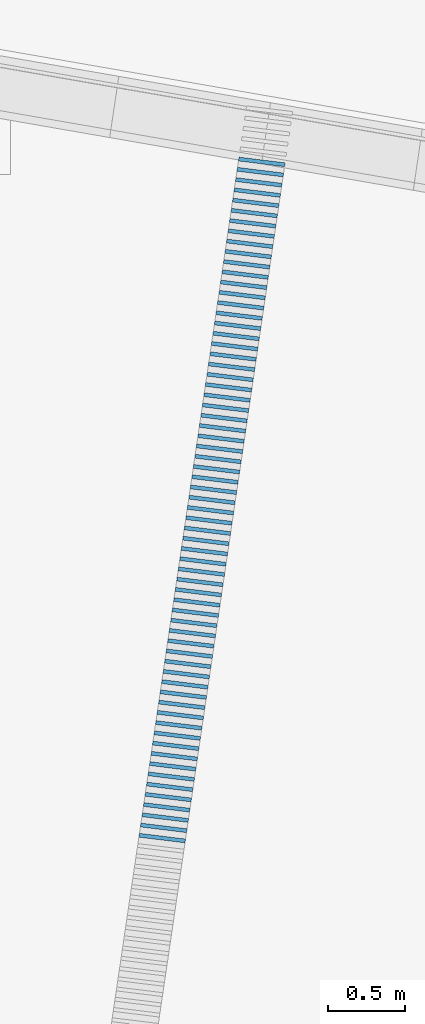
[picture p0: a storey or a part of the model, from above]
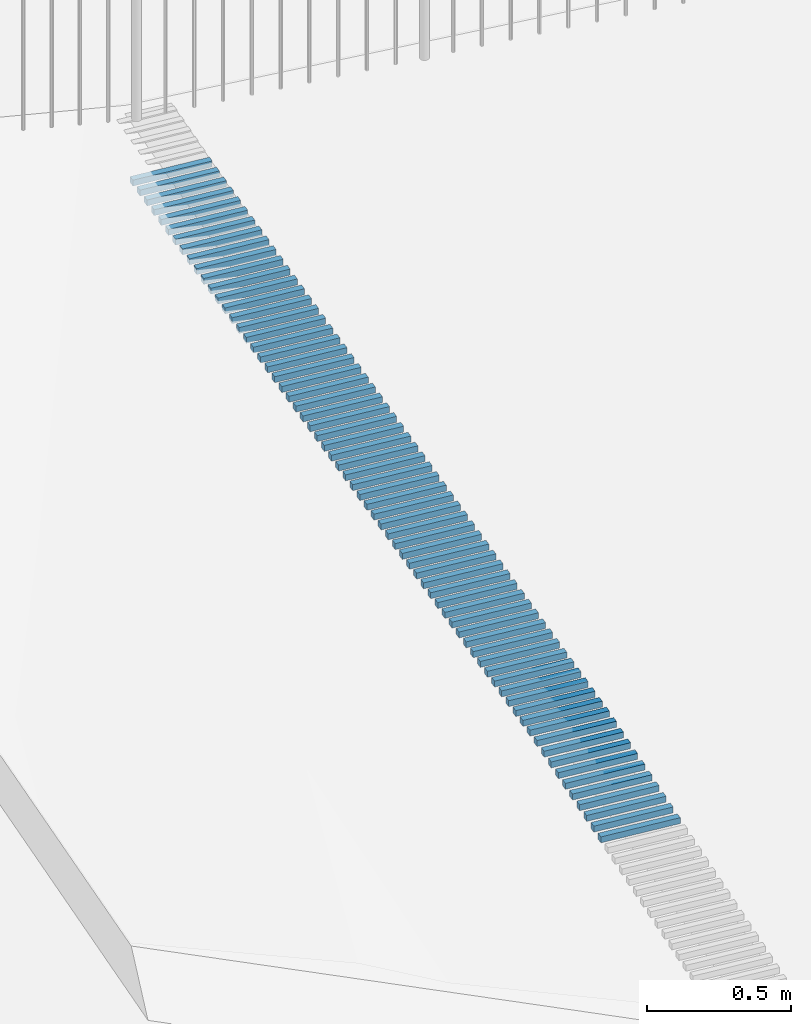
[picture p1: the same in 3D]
Properties of the parts of a building model (IFC4), part 2 of 4

# IfcBuildingElementProxy: Limite north · gabião 20 · pedra aparente
Pset_CasaProvenance - DesignSource: Casa Sobreposta / configuration.json; ReferenceFile: 260617_CasaDFL_Estrutura_Terreno.ifc; ConstructionBasis: DESIGN_ASSUMPTION; Note: R07 concept geometry; dimensions and connections not structurally verified.

# IfcBuildingElementProxy: Limite north · gabião 21 · cesto galvanizado
In: Lares · Rua das Mercês · artigo 4771
PredefinedType: USERDEFINED; Material: Aço galvanizado / Stahl verzinkt
Pset_CasaProvenance - DesignSource: Casa Sobreposta / configuration.json; ReferenceFile: 260617_CasaDFL_Estrutura_Terreno.ifc; ConstructionBasis: DESIGN_ASSUMPTION; Note: R07 concept geometry; dimensions and connections not structurally verified.

# IfcBuildingElementProxy: Limite north · gabião 21 · pedra aparente
In: Lares · Rua das Mercês · artigo 4771
PredefinedType: USERDEFINED; Material: Gabião · pedra irregular
Pset_CasaProvenance - DesignSource: Casa Sobreposta / configuration.json; ReferenceFile: 260617_CasaDFL_Estrutura_Terreno.ifc; ConstructionBasis: DESIGN_ASSUMPTION; Note: R07 concept geometry; dimensions and connections not structurally verified.

# IfcBuildingElementProxy: Limite north · gabião 22 · cesto galvanizado
In: Lares · Rua das Mercês · artigo 4771
PredefinedType: USERDEFINED; Material: Aço galvanizado / Stahl verzinkt
Pset_CasaProvenance - DesignSource: Casa Sobreposta / configuration.json; ReferenceFile: 260617_CasaDFL_Estrutura_Terreno.ifc; ConstructionBasis: DESIGN_ASSUMPTION; Note: R07 concept geometry; dimensions and connections not structurally verified.

# IfcBuildingElementProxy: Limite north · gabião 22 · pedra aparente
In: Lares · Rua das Mercês · artigo 4771
PredefinedType: USERDEFINED; Material: Gabião · pedra irregular
Pset_CasaProvenance - DesignSource: Casa Sobreposta / configuration.json; ReferenceFile: 260617_CasaDFL_Estrutura_Terreno.ifc; ConstructionBasis: DESIGN_ASSUMPTION; Note: R07 concept geometry; dimensions and connections not structurally verified.

# IfcBuildingElementProxy: Limite north · gabião 23 · cesto galvanizado
In: Lares · Rua das Mercês · artigo 4771
PredefinedType: USERDEFINED; Material: Aço galvanizado / Stahl verzinkt
Pset_CasaProvenance - DesignSource: Casa Sobreposta / configuration.json; ReferenceFile: 260617_CasaDFL_Estrutura_Terreno.ifc; ConstructionBasis: DESIGN_ASSUMPTION; Note: R07 concept geometry; dimensions and connections not structurally verified.

# IfcBuildingElementProxy: Limite north · gabião 23 · pedra aparente
In: Lares · Rua das Mercês · artigo 4771
PredefinedType: USERDEFINED; Material: Gabião · pedra irregular
Pset_CasaProvenance - DesignSource: Casa Sobreposta / configuration.json; ReferenceFile: 260617_CasaDFL_Estrutura_Terreno.ifc; ConstructionBasis: DESIGN_ASSUMPTION; Note: R07 concept geometry; dimensions and connections not structurally verified.

# IfcBuildingElementProxy: Limite north · gabião 24 · cesto galvanizado
In: Lares · Rua das Mercês · artigo 4771
PredefinedType: USERDEFINED; Material: Aço galvanizado / Stahl verzinkt
Pset_CasaProvenance - DesignSource: Casa Sobreposta / configuration.json; ReferenceFile: 260617_CasaDFL_Estrutura_Terreno.ifc; ConstructionBasis: DESIGN_ASSUMPTION; Note: R07 concept geometry; dimensions and connections not structurally verified.

# IfcBuildingElementProxy: Limite north · gabião 24 · pedra aparente
In: Lares · Rua das Mercês · artigo 4771
PredefinedType: USERDEFINED; Material: Gabião · pedra irregular
Pset_CasaProvenance - DesignSource: Casa Sobreposta / configuration.json; ReferenceFile: 260617_CasaDFL_Estrutura_Terreno.ifc; ConstructionBasis: DESIGN_ASSUMPTION; Note: R07 concept geometry; dimensions and connections not structurally verified.

# IfcBuildingElementProxy: Limite north · gabião 25 · cesto galvanizado
In: Lares · Rua das Mercês · artigo 4771
PredefinedType: USERDEFINED; Material: Aço galvanizado / Stahl verzinkt
Pset_CasaProvenance - DesignSource: Casa Sobreposta / configuration.json; ReferenceFile: 260617_CasaDFL_Estrutura_Terreno.ifc; ConstructionBasis: DESIGN_ASSUMPTION; Note: R07 concept geometry; dimensions and connections not structurally verified.

# IfcBuildingElementProxy: Limite north · gabião 25 · pedra aparente
In: Lares · Rua das Mercês · artigo 4771
PredefinedType: USERDEFINED; Material: Gabião · pedra irregular
Pset_CasaProvenance - DesignSource: Casa Sobreposta / configuration.json; ReferenceFile: 260617_CasaDFL_Estrutura_Terreno.ifc; ConstructionBasis: DESIGN_ASSUMPTION; Note: R07 concept geometry; dimensions and connections not structurally verified.

# IfcBuildingElementProxy: Limite north · gabião 26 · cesto galvanizado
In: Lares · Rua das Mercês · artigo 4771
PredefinedType: USERDEFINED; Material: Aço galvanizado / Stahl verzinkt
Pset_CasaProvenance - DesignSource: Casa Sobreposta / configuration.json; ReferenceFile: 260617_CasaDFL_Estrutura_Terreno.ifc; ConstructionBasis: DESIGN_ASSUMPTION; Note: R07 concept geometry; dimensions and connections not structurally verified.

# IfcBuildingElementProxy: Limite north · gabião 26 · pedra aparente
In: Lares · Rua das Mercês · artigo 4771
PredefinedType: USERDEFINED; Material: Gabião · pedra irregular
Pset_CasaProvenance - DesignSource: Casa Sobreposta / configuration.json; ReferenceFile: 260617_CasaDFL_Estrutura_Terreno.ifc; ConstructionBasis: DESIGN_ASSUMPTION; Note: R07 concept geometry; dimensions and connections not structurally verified.

# IfcBuildingElementProxy: Limite north · gabião 27 · cesto galvanizado
In: Lares · Rua das Mercês · artigo 4771
PredefinedType: USERDEFINED; Material: Aço galvanizado / Stahl verzinkt
Pset_CasaProvenance - DesignSource: Casa Sobreposta / configuration.json; ReferenceFile: 260617_CasaDFL_Estrutura_Terreno.ifc; ConstructionBasis: DESIGN_ASSUMPTION; Note: R07 concept geometry; dimensions and connections not structurally verified.

# IfcBuildingElementProxy: Limite north · gabião 27 · pedra aparente
In: Lares · Rua das Mercês · artigo 4771
PredefinedType: USERDEFINED; Material: Gabião · pedra irregular
Pset_CasaProvenance - DesignSource: Casa Sobreposta / configuration.json; ReferenceFile: 260617_CasaDFL_Estrutura_Terreno.ifc; ConstructionBasis: DESIGN_ASSUMPTION; Note: R07 concept geometry; dimensions and connections not structurally verified.

# IfcBuildingElementProxy: Limite north · gabião 4 · cesto galvanizado
In: Lares · Rua das Mercês · artigo 4771
PredefinedType: USERDEFINED; Material: Aço galvanizado / Stahl verzinkt
Pset_CasaProvenance - DesignSource: Casa Sobreposta / configuration.json; ReferenceFile: 260617_CasaDFL_Estrutura_Terreno.ifc; ConstructionBasis: DESIGN_ASSUMPTION; Note: R07 concept geometry; dimensions and connections not structurally verified.

# IfcBuildingElementProxy: Limite north · gabião 4 · pedra aparente
In: Lares · Rua das Mercês · artigo 4771
PredefinedType: USERDEFINED; Material: Gabião · pedra irregular
Pset_CasaProvenance - DesignSource: Casa Sobreposta / configuration.json; ReferenceFile: 260617_CasaDFL_Estrutura_Terreno.ifc; ConstructionBasis: DESIGN_ASSUMPTION; Note: R07 concept geometry; dimensions and connections not structurally verified.

# IfcBuildingElementProxy: Limite north · gabião 5 · cesto galvanizado
In: Lares · Rua das Mercês · artigo 4771
PredefinedType: USERDEFINED; Material: Aço galvanizado / Stahl verzinkt
Pset_CasaProvenance - DesignSource: Casa Sobreposta / configuration.json; ReferenceFile: 260617_CasaDFL_Estrutura_Terreno.ifc; ConstructionBasis: DESIGN_ASSUMPTION; Note: R07 concept geometry; dimensions and connections not structurally verified.

# IfcBuildingElementProxy: Limite north · gabião 5 · pedra aparente
In: Lares · Rua das Mercês · artigo 4771
PredefinedType: USERDEFINED; Material: Gabião · pedra irregular
Pset_CasaProvenance - DesignSource: Casa Sobreposta / configuration.json; ReferenceFile: 260617_CasaDFL_Estrutura_Terreno.ifc; ConstructionBasis: DESIGN_ASSUMPTION; Note: R07 concept geometry; dimensions and connections not structurally verified.

# IfcBuildingElementProxy: Limite north · gabião 6 · cesto galvanizado
In: Lares · Rua das Mercês · artigo 4771
PredefinedType: USERDEFINED; Material: Aço galvanizado / Stahl verzinkt
Pset_CasaProvenance - DesignSource: Casa Sobreposta / configuration.json; ReferenceFile: 260617_CasaDFL_Estrutura_Terreno.ifc; ConstructionBasis: DESIGN_ASSUMPTION; Note: R07 concept geometry; dimensions and connections not structurally verified.

# IfcBuildingElementProxy: Limite north · gabião 6 · pedra aparente
In: Lares · Rua das Mercês · artigo 4771
PredefinedType: USERDEFINED; Material: Gabião · pedra irregular
Pset_CasaProvenance - DesignSource: Casa Sobreposta / configuration.json; ReferenceFile: 260617_CasaDFL_Estrutura_Terreno.ifc; ConstructionBasis: DESIGN_ASSUMPTION; Note: R07 concept geometry; dimensions and connections not structurally verified.

# IfcBuildingElementProxy: Limite north · gabião 7 · cesto galvanizado
In: Lares · Rua das Mercês · artigo 4771
PredefinedType: USERDEFINED; Material: Aço galvanizado / Stahl verzinkt
Pset_CasaProvenance - DesignSource: Casa Sobreposta / configuration.json; ReferenceFile: 260617_CasaDFL_Estrutura_Terreno.ifc; ConstructionBasis: DESIGN_ASSUMPTION; Note: R07 concept geometry; dimensions and connections not structurally verified.

# IfcBuildingElementProxy: Limite north · gabião 7 · pedra aparente
In: Lares · Rua das Mercês · artigo 4771
PredefinedType: USERDEFINED; Material: Gabião · pedra irregular
Pset_CasaProvenance - DesignSource: Casa Sobreposta / configuration.json; ReferenceFile: 260617_CasaDFL_Estrutura_Terreno.ifc; ConstructionBasis: DESIGN_ASSUMPTION; Note: R07 concept geometry; dimensions and connections not structurally verified.

# IfcBuildingElementProxy: Limite north · gabião 8 · cesto galvanizado
In: Lares · Rua das Mercês · artigo 4771
PredefinedType: USERDEFINED; Material: Aço galvanizado / Stahl verzinkt
Pset_CasaProvenance - DesignSource: Casa Sobreposta / configuration.json; ReferenceFile: 260617_CasaDFL_Estrutura_Terreno.ifc; ConstructionBasis: DESIGN_ASSUMPTION; Note: R07 concept geometry; dimensions and connections not structurally verified.

# IfcBuildingElementProxy: Limite north · gabião 8 · pedra aparente
In: Lares · Rua das Mercês · artigo 4771
PredefinedType: USERDEFINED; Material: Gabião · pedra irregular
Pset_CasaProvenance - DesignSource: Casa Sobreposta / configuration.json; ReferenceFile: 260617_CasaDFL_Estrutura_Terreno.ifc; ConstructionBasis: DESIGN_ASSUMPTION; Note: R07 concept geometry; dimensions and connections not structurally verified.

# IfcBuildingElementProxy: Limite north · gabião 9 · cesto galvanizado
In: Lares · Rua das Mercês · artigo 4771
PredefinedType: USERDEFINED; Material: Aço galvanizado / Stahl verzinkt
Pset_CasaProvenance - DesignSource: Casa Sobreposta / configuration.json; ReferenceFile: 260617_CasaDFL_Estrutura_Terreno.ifc; ConstructionBasis: DESIGN_ASSUMPTION; Note: R07 concept geometry; dimensions and connections not structurally verified.

# IfcBuildingElementProxy: Limite north · gabião 9 · pedra aparente
In: Lares · Rua das Mercês · artigo 4771
PredefinedType: USERDEFINED; Material: Gabião · pedra irregular
Pset_CasaProvenance - DesignSource: Casa Sobreposta / configuration.json; ReferenceFile: 260617_CasaDFL_Estrutura_Terreno.ifc; ConstructionBasis: DESIGN_ASSUMPTION; Note: R07 concept geometry; dimensions and connections not structurally verified.

# IfcBuildingElementProxy: Limite north · vala de interceção (37)
In: Lares · Rua das Mercês · artigo 4771
PredefinedType: USERDEFINED; Material: Brita drenante
Pset_CasaProvenance - DesignSource: Casa Sobreposta / configuration.json; ReferenceFile: 260617_CasaDFL_Estrutura_Terreno.ifc; ConstructionBasis: DESIGN_ASSUMPTION

# IfcBuildingElementProxy: Limite south · gabião 1 · cesto galvanizado
In: Lares · Rua das Mercês · artigo 4771
PredefinedType: USERDEFINED; Material: Aço galvanizado / Stahl verzinkt
Pset_CasaProvenance - DesignSource: Casa Sobreposta / configuration.json; ReferenceFile: 260617_CasaDFL_Estrutura_Terreno.ifc; ConstructionBasis: DESIGN_ASSUMPTION; Note: R07 concept geometry; dimensions and connections not structurally verified.

# IfcBuildingElementProxy: Limite south · gabião 1 · pedra aparente
In: Lares · Rua das Mercês · artigo 4771
PredefinedType: USERDEFINED; Material: Gabião · pedra irregular
Pset_CasaProvenance - DesignSource: Casa Sobreposta / configuration.json; ReferenceFile: 260617_CasaDFL_Estrutura_Terreno.ifc; ConstructionBasis: DESIGN_ASSUMPTION; Note: R07 concept geometry; dimensions and connections not structurally verified.

# IfcBuildingElementProxy: Limite south · gabião 10 · cesto galvanizado
In: Lares · Rua das Mercês · artigo 4771
PredefinedType: USERDEFINED; Material: Aço galvanizado / Stahl verzinkt
Pset_CasaProvenance - DesignSource: Casa Sobreposta / configuration.json; ReferenceFile: 260617_CasaDFL_Estrutura_Terreno.ifc; ConstructionBasis: DESIGN_ASSUMPTION; Note: R07 concept geometry; dimensions and connections not structurally verified.

# IfcBuildingElementProxy: Limite south · gabião 10 · pedra aparente
In: Lares · Rua das Mercês · artigo 4771
PredefinedType: USERDEFINED; Material: Gabião · pedra irregular
Pset_CasaProvenance - DesignSource: Casa Sobreposta / configuration.json; ReferenceFile: 260617_CasaDFL_Estrutura_Terreno.ifc; ConstructionBasis: DESIGN_ASSUMPTION; Note: R07 concept geometry; dimensions and connections not structurally verified.

# IfcBuildingElementProxy: Limite south · gabião 11 · cesto galvanizado
In: Lares · Rua das Mercês · artigo 4771
PredefinedType: USERDEFINED; Material: Aço galvanizado / Stahl verzinkt
Pset_CasaProvenance - DesignSource: Casa Sobreposta / configuration.json; ReferenceFile: 260617_CasaDFL_Estrutura_Terreno.ifc; ConstructionBasis: DESIGN_ASSUMPTION; Note: R07 concept geometry; dimensions and connections not structurally verified.

# IfcBuildingElementProxy: Limite south · gabião 11 · pedra aparente
In: Lares · Rua das Mercês · artigo 4771
PredefinedType: USERDEFINED; Material: Gabião · pedra irregular
Pset_CasaProvenance - DesignSource: Casa Sobreposta / configuration.json; ReferenceFile: 260617_CasaDFL_Estrutura_Terreno.ifc; ConstructionBasis: DESIGN_ASSUMPTION; Note: R07 concept geometry; dimensions and connections not structurally verified.

# IfcBuildingElementProxy: Limite south · gabião 12 · cesto galvanizado
In: Lares · Rua das Mercês · artigo 4771
PredefinedType: USERDEFINED; Material: Aço galvanizado / Stahl verzinkt
Pset_CasaProvenance - DesignSource: Casa Sobreposta / configuration.json; ReferenceFile: 260617_CasaDFL_Estrutura_Terreno.ifc; ConstructionBasis: DESIGN_ASSUMPTION; Note: R07 concept geometry; dimensions and connections not structurally verified.

# IfcBuildingElementProxy: Limite south · gabião 12 · pedra aparente
In: Lares · Rua das Mercês · artigo 4771
PredefinedType: USERDEFINED; Material: Gabião · pedra irregular
Pset_CasaProvenance - DesignSource: Casa Sobreposta / configuration.json; ReferenceFile: 260617_CasaDFL_Estrutura_Terreno.ifc; ConstructionBasis: DESIGN_ASSUMPTION; Note: R07 concept geometry; dimensions and connections not structurally verified.

# IfcBuildingElementProxy: Limite south · gabião 13 · cesto galvanizado
In: Lares · Rua das Mercês · artigo 4771
PredefinedType: USERDEFINED; Material: Aço galvanizado / Stahl verzinkt
Pset_CasaProvenance - DesignSource: Casa Sobreposta / configuration.json; ReferenceFile: 260617_CasaDFL_Estrutura_Terreno.ifc; ConstructionBasis: DESIGN_ASSUMPTION; Note: R07 concept geometry; dimensions and connections not structurally verified.

# IfcBuildingElementProxy: Limite south · gabião 13 · pedra aparente
In: Lares · Rua das Mercês · artigo 4771
PredefinedType: USERDEFINED; Material: Gabião · pedra irregular
Pset_CasaProvenance - DesignSource: Casa Sobreposta / configuration.json; ReferenceFile: 260617_CasaDFL_Estrutura_Terreno.ifc; ConstructionBasis: DESIGN_ASSUMPTION; Note: R07 concept geometry; dimensions and connections not structurally verified.

# IfcBuildingElementProxy: Limite south · gabião 14 · cesto galvanizado
In: Lares · Rua das Mercês · artigo 4771
PredefinedType: USERDEFINED; Material: Aço galvanizado / Stahl verzinkt
Pset_CasaProvenance - DesignSource: Casa Sobreposta / configuration.json; ReferenceFile: 260617_CasaDFL_Estrutura_Terreno.ifc; ConstructionBasis: DESIGN_ASSUMPTION; Note: R07 concept geometry; dimensions and connections not structurally verified.

# IfcBuildingElementProxy: Limite south · gabião 14 · pedra aparente
In: Lares · Rua das Mercês · artigo 4771
PredefinedType: USERDEFINED; Material: Gabião · pedra irregular
Pset_CasaProvenance - DesignSource: Casa Sobreposta / configuration.json; ReferenceFile: 260617_CasaDFL_Estrutura_Terreno.ifc; ConstructionBasis: DESIGN_ASSUMPTION; Note: R07 concept geometry; dimensions and connections not structurally verified.

# IfcBuildingElementProxy: Limite south · gabião 15 · cesto galvanizado
In: Lares · Rua das Mercês · artigo 4771
PredefinedType: USERDEFINED; Material: Aço galvanizado / Stahl verzinkt
Pset_CasaProvenance - DesignSource: Casa Sobreposta / configuration.json; ReferenceFile: 260617_CasaDFL_Estrutura_Terreno.ifc; ConstructionBasis: DESIGN_ASSUMPTION; Note: R07 concept geometry; dimensions and connections not structurally verified.

# IfcBuildingElementProxy: Limite south · gabião 15 · pedra aparente
In: Lares · Rua das Mercês · artigo 4771
PredefinedType: USERDEFINED; Material: Gabião · pedra irregular
Pset_CasaProvenance - DesignSource: Casa Sobreposta / configuration.json; ReferenceFile: 260617_CasaDFL_Estrutura_Terreno.ifc; ConstructionBasis: DESIGN_ASSUMPTION; Note: R07 concept geometry; dimensions and connections not structurally verified.

# IfcBuildingElementProxy: Limite south · gabião 16 · cesto galvanizado
In: Lares · Rua das Mercês · artigo 4771
PredefinedType: USERDEFINED; Material: Aço galvanizado / Stahl verzinkt
Pset_CasaProvenance - DesignSource: Casa Sobreposta / configuration.json; ReferenceFile: 260617_CasaDFL_Estrutura_Terreno.ifc; ConstructionBasis: DESIGN_ASSUMPTION; Note: R07 concept geometry; dimensions and connections not structurally verified.

# IfcBuildingElementProxy: Limite south · gabião 16 · pedra aparente
In: Lares · Rua das Mercês · artigo 4771
PredefinedType: USERDEFINED; Material: Gabião · pedra irregular
Pset_CasaProvenance - DesignSource: Casa Sobreposta / configuration.json; ReferenceFile: 260617_CasaDFL_Estrutura_Terreno.ifc; ConstructionBasis: DESIGN_ASSUMPTION; Note: R07 concept geometry; dimensions and connections not structurally verified.

# IfcBuildingElementProxy: Limite south · gabião 17 · cesto galvanizado
In: Lares · Rua das Mercês · artigo 4771
PredefinedType: USERDEFINED; Material: Aço galvanizado / Stahl verzinkt
Pset_CasaProvenance - DesignSource: Casa Sobreposta / configuration.json; ReferenceFile: 260617_CasaDFL_Estrutura_Terreno.ifc; ConstructionBasis: DESIGN_ASSUMPTION; Note: R07 concept geometry; dimensions and connections not structurally verified.

# IfcBuildingElementProxy: Limite south · gabião 17 · pedra aparente
In: Lares · Rua das Mercês · artigo 4771
PredefinedType: USERDEFINED; Material: Gabião · pedra irregular
Pset_CasaProvenance - DesignSource: Casa Sobreposta / configuration.json; ReferenceFile: 260617_CasaDFL_Estrutura_Terreno.ifc; ConstructionBasis: DESIGN_ASSUMPTION; Note: R07 concept geometry; dimensions and connections not structurally verified.

# IfcBuildingElementProxy: Limite south · gabião 18 · cesto galvanizado
In: Lares · Rua das Mercês · artigo 4771
PredefinedType: USERDEFINED; Material: Aço galvanizado / Stahl verzinkt
Pset_CasaProvenance - DesignSource: Casa Sobreposta / configuration.json; ReferenceFile: 260617_CasaDFL_Estrutura_Terreno.ifc; ConstructionBasis: DESIGN_ASSUMPTION; Note: R07 concept geometry; dimensions and connections not structurally verified.

# IfcBuildingElementProxy: Limite south · gabião 18 · pedra aparente
In: Lares · Rua das Mercês · artigo 4771
PredefinedType: USERDEFINED; Material: Gabião · pedra irregular
Pset_CasaProvenance - DesignSource: Casa Sobreposta / configuration.json; ReferenceFile: 260617_CasaDFL_Estrutura_Terreno.ifc; ConstructionBasis: DESIGN_ASSUMPTION; Note: R07 concept geometry; dimensions and connections not structurally verified.

# IfcBuildingElementProxy: Limite south · gabião 19 · cesto galvanizado
In: Lares · Rua das Mercês · artigo 4771
PredefinedType: USERDEFINED; Material: Aço galvanizado / Stahl verzinkt
Pset_CasaProvenance - DesignSource: Casa Sobreposta / configuration.json; ReferenceFile: 260617_CasaDFL_Estrutura_Terreno.ifc; ConstructionBasis: DESIGN_ASSUMPTION; Note: R07 concept geometry; dimensions and connections not structurally verified.

# IfcBuildingElementProxy: Limite south · gabião 19 · pedra aparente
In: Lares · Rua das Mercês · artigo 4771
PredefinedType: USERDEFINED; Material: Gabião · pedra irregular
Pset_CasaProvenance - DesignSource: Casa Sobreposta / configuration.json; ReferenceFile: 260617_CasaDFL_Estrutura_Terreno.ifc; ConstructionBasis: DESIGN_ASSUMPTION; Note: R07 concept geometry; dimensions and connections not structurally verified.

# IfcBuildingElementProxy: Limite south · gabião 2 · cesto galvanizado
In: Lares · Rua das Mercês · artigo 4771
PredefinedType: USERDEFINED; Material: Aço galvanizado / Stahl verzinkt
Pset_CasaProvenance - DesignSource: Casa Sobreposta / configuration.json; ReferenceFile: 260617_CasaDFL_Estrutura_Terreno.ifc; ConstructionBasis: DESIGN_ASSUMPTION; Note: R07 concept geometry; dimensions and connections not structurally verified.

# IfcBuildingElementProxy: Limite south · gabião 2 · pedra aparente
In: Lares · Rua das Mercês · artigo 4771
PredefinedType: USERDEFINED; Material: Gabião · pedra irregular
Pset_CasaProvenance - DesignSource: Casa Sobreposta / configuration.json; ReferenceFile: 260617_CasaDFL_Estrutura_Terreno.ifc; ConstructionBasis: DESIGN_ASSUMPTION; Note: R07 concept geometry; dimensions and connections not structurally verified.

# IfcBuildingElementProxy: Limite south · gabião 20 · cesto galvanizado
In: Lares · Rua das Mercês · artigo 4771
PredefinedType: USERDEFINED; Material: Aço galvanizado / Stahl verzinkt
Pset_CasaProvenance - DesignSource: Casa Sobreposta / configuration.json; ReferenceFile: 260617_CasaDFL_Estrutura_Terreno.ifc; ConstructionBasis: DESIGN_ASSUMPTION; Note: R07 concept geometry; dimensions and connections not structurally verified.

# IfcBuildingElementProxy: Limite south · gabião 20 · pedra aparente
In: Lares · Rua das Mercês · artigo 4771
PredefinedType: USERDEFINED; Material: Gabião · pedra irregular
Pset_CasaProvenance - DesignSource: Casa Sobreposta / configuration.json; ReferenceFile: 260617_CasaDFL_Estrutura_Terreno.ifc; ConstructionBasis: DESIGN_ASSUMPTION; Note: R07 concept geometry; dimensions and connections not structurally verified.

# IfcBuildingElementProxy: Limite south · gabião 21 · cesto galvanizado
In: Lares · Rua das Mercês · artigo 4771
PredefinedType: USERDEFINED; Material: Aço galvanizado / Stahl verzinkt
Pset_CasaProvenance - DesignSource: Casa Sobreposta / configuration.json; ReferenceFile: 260617_CasaDFL_Estrutura_Terreno.ifc; ConstructionBasis: DESIGN_ASSUMPTION; Note: R07 concept geometry; dimensions and connections not structurally verified.

# IfcBuildingElementProxy: Limite south · gabião 21 · pedra aparente
In: Lares · Rua das Mercês · artigo 4771
PredefinedType: USERDEFINED; Material: Gabião · pedra irregular
Pset_CasaProvenance - DesignSource: Casa Sobreposta / configuration.json; ReferenceFile: 260617_CasaDFL_Estrutura_Terreno.ifc; ConstructionBasis: DESIGN_ASSUMPTION; Note: R07 concept geometry; dimensions and connections not structurally verified.

# IfcBuildingElementProxy: Limite south · gabião 22 · cesto galvanizado
In: Lares · Rua das Mercês · artigo 4771
PredefinedType: USERDEFINED; Material: Aço galvanizado / Stahl verzinkt
Pset_CasaProvenance - DesignSource: Casa Sobreposta / configuration.json; ReferenceFile: 260617_CasaDFL_Estrutura_Terreno.ifc; ConstructionBasis: DESIGN_ASSUMPTION; Note: R07 concept geometry; dimensions and connections not structurally verified.

# IfcBuildingElementProxy: Limite south · gabião 22 · pedra aparente
In: Lares · Rua das Mercês · artigo 4771
PredefinedType: USERDEFINED; Material: Gabião · pedra irregular
Pset_CasaProvenance - DesignSource: Casa Sobreposta / configuration.json; ReferenceFile: 260617_CasaDFL_Estrutura_Terreno.ifc; ConstructionBasis: DESIGN_ASSUMPTION; Note: R07 concept geometry; dimensions and connections not structurally verified.

# IfcBuildingElementProxy: Limite south · gabião 23 · cesto galvanizado
In: Lares · Rua das Mercês · artigo 4771
PredefinedType: USERDEFINED; Material: Aço galvanizado / Stahl verzinkt
Pset_CasaProvenance - DesignSource: Casa Sobreposta / configuration.json; ReferenceFile: 260617_CasaDFL_Estrutura_Terreno.ifc; ConstructionBasis: DESIGN_ASSUMPTION; Note: R07 concept geometry; dimensions and connections not structurally verified.

# IfcBuildingElementProxy: Limite south · gabião 23 · pedra aparente
In: Lares · Rua das Mercês · artigo 4771
PredefinedType: USERDEFINED; Material: Gabião · pedra irregular
Pset_CasaProvenance - DesignSource: Casa Sobreposta / configuration.json; ReferenceFile: 260617_CasaDFL_Estrutura_Terreno.ifc; ConstructionBasis: DESIGN_ASSUMPTION; Note: R07 concept geometry; dimensions and connections not structurally verified.

# IfcBuildingElementProxy: Limite south · gabião 24 · cesto galvanizado
In: Lares · Rua das Mercês · artigo 4771
PredefinedType: USERDEFINED; Material: Aço galvanizado / Stahl verzinkt
Pset_CasaProvenance - DesignSource: Casa Sobreposta / configuration.json; ReferenceFile: 260617_CasaDFL_Estrutura_Terreno.ifc; ConstructionBasis: DESIGN_ASSUMPTION; Note: R07 concept geometry; dimensions and connections not structurally verified.

# IfcBuildingElementProxy: Limite south · gabião 24 · pedra aparente
In: Lares · Rua das Mercês · artigo 4771
PredefinedType: USERDEFINED; Material: Gabião · pedra irregular
Pset_CasaProvenance - DesignSource: Casa Sobreposta / configuration.json; ReferenceFile: 260617_CasaDFL_Estrutura_Terreno.ifc; ConstructionBasis: DESIGN_ASSUMPTION; Note: R07 concept geometry; dimensions and connections not structurally verified.

# IfcBuildingElementProxy: Limite south · gabião 25 · cesto galvanizado
In: Lares · Rua das Mercês · artigo 4771
PredefinedType: USERDEFINED; Material: Aço galvanizado / Stahl verzinkt
Pset_CasaProvenance - DesignSource: Casa Sobreposta / configuration.json; ReferenceFile: 260617_CasaDFL_Estrutura_Terreno.ifc; ConstructionBasis: DESIGN_ASSUMPTION; Note: R07 concept geometry; dimensions and connections not structurally verified.

# IfcBuildingElementProxy: Limite south · gabião 25 · pedra aparente
In: Lares · Rua das Mercês · artigo 4771
PredefinedType: USERDEFINED; Material: Gabião · pedra irregular
Pset_CasaProvenance - DesignSource: Casa Sobreposta / configuration.json; ReferenceFile: 260617_CasaDFL_Estrutura_Terreno.ifc; ConstructionBasis: DESIGN_ASSUMPTION; Note: R07 concept geometry; dimensions and connections not structurally verified.

# IfcBuildingElementProxy: Limite south · gabião 26 · cesto galvanizado
In: Lares · Rua das Mercês · artigo 4771
PredefinedType: USERDEFINED; Material: Aço galvanizado / Stahl verzinkt
Pset_CasaProvenance - DesignSource: Casa Sobreposta / configuration.json; ReferenceFile: 260617_CasaDFL_Estrutura_Terreno.ifc; ConstructionBasis: DESIGN_ASSUMPTION; Note: R07 concept geometry; dimensions and connections not structurally verified.

# IfcBuildingElementProxy: Limite south · gabião 26 · pedra aparente
In: Lares · Rua das Mercês · artigo 4771
PredefinedType: USERDEFINED; Material: Gabião · pedra irregular
Pset_CasaProvenance - DesignSource: Casa Sobreposta / configuration.json; ReferenceFile: 260617_CasaDFL_Estrutura_Terreno.ifc; ConstructionBasis: DESIGN_ASSUMPTION; Note: R07 concept geometry; dimensions and connections not structurally verified.

# IfcBuildingElementProxy: Limite south · gabião 27 · cesto galvanizado
In: Lares · Rua das Mercês · artigo 4771
PredefinedType: USERDEFINED; Material: Aço galvanizado / Stahl verzinkt
Pset_CasaProvenance - DesignSource: Casa Sobreposta / configuration.json; ReferenceFile: 260617_CasaDFL_Estrutura_Terreno.ifc; ConstructionBasis: DESIGN_ASSUMPTION; Note: R07 concept geometry; dimensions and connections not structurally verified.

# IfcBuildingElementProxy: Limite south · gabião 27 · pedra aparente
In: Lares · Rua das Mercês · artigo 4771
PredefinedType: USERDEFINED; Material: Gabião · pedra irregular
Pset_CasaProvenance - DesignSource: Casa Sobreposta / configuration.json; ReferenceFile: 260617_CasaDFL_Estrutura_Terreno.ifc; ConstructionBasis: DESIGN_ASSUMPTION; Note: R07 concept geometry; dimensions and connections not structurally verified.

# IfcBuildingElementProxy: Limite south · gabião 28 · cesto galvanizado
In: Lares · Rua das Mercês · artigo 4771
PredefinedType: USERDEFINED; Material: Aço galvanizado / Stahl verzinkt
Pset_CasaProvenance - DesignSource: Casa Sobreposta / configuration.json; ReferenceFile: 260617_CasaDFL_Estrutura_Terreno.ifc; ConstructionBasis: DESIGN_ASSUMPTION; Note: R07 concept geometry; dimensions and connections not structurally verified.

# IfcBuildingElementProxy: Limite south · gabião 28 · pedra aparente
In: Lares · Rua das Mercês · artigo 4771
PredefinedType: USERDEFINED; Material: Gabião · pedra irregular
Pset_CasaProvenance - DesignSource: Casa Sobreposta / configuration.json; ReferenceFile: 260617_CasaDFL_Estrutura_Terreno.ifc; ConstructionBasis: DESIGN_ASSUMPTION; Note: R07 concept geometry; dimensions and connections not structurally verified.

# IfcBuildingElementProxy: Limite south · gabião 29 · cesto galvanizado
In: Lares · Rua das Mercês · artigo 4771
PredefinedType: USERDEFINED; Material: Aço galvanizado / Stahl verzinkt
Pset_CasaProvenance - DesignSource: Casa Sobreposta / configuration.json; ReferenceFile: 260617_CasaDFL_Estrutura_Terreno.ifc; ConstructionBasis: DESIGN_ASSUMPTION; Note: R07 concept geometry; dimensions and connections not structurally verified.

# IfcBuildingElementProxy: Limite south · gabião 29 · pedra aparente
In: Lares · Rua das Mercês · artigo 4771
PredefinedType: USERDEFINED; Material: Gabião · pedra irregular
Pset_CasaProvenance - DesignSource: Casa Sobreposta / configuration.json; ReferenceFile: 260617_CasaDFL_Estrutura_Terreno.ifc; ConstructionBasis: DESIGN_ASSUMPTION; Note: R07 concept geometry; dimensions and connections not structurally verified.

# IfcBuildingElementProxy: Limite south · gabião 3 · cesto galvanizado
In: Lares · Rua das Mercês · artigo 4771
PredefinedType: USERDEFINED; Material: Aço galvanizado / Stahl verzinkt
Pset_CasaProvenance - DesignSource: Casa Sobreposta / configuration.json; ReferenceFile: 260617_CasaDFL_Estrutura_Terreno.ifc; ConstructionBasis: DESIGN_ASSUMPTION; Note: R07 concept geometry; dimensions and connections not structurally verified.

# IfcBuildingElementProxy: Limite south · gabião 3 · pedra aparente
In: Lares · Rua das Mercês · artigo 4771
PredefinedType: USERDEFINED; Material: Gabião · pedra irregular
Pset_CasaProvenance - DesignSource: Casa Sobreposta / configuration.json; ReferenceFile: 260617_CasaDFL_Estrutura_Terreno.ifc; ConstructionBasis: DESIGN_ASSUMPTION; Note: R07 concept geometry; dimensions and connections not structurally verified.

# IfcBuildingElementProxy: Limite south · gabião 30 · cesto galvanizado
In: Lares · Rua das Mercês · artigo 4771
PredefinedType: USERDEFINED; Material: Aço galvanizado / Stahl verzinkt
Pset_CasaProvenance - DesignSource: Casa Sobreposta / configuration.json; ReferenceFile: 260617_CasaDFL_Estrutura_Terreno.ifc; ConstructionBasis: DESIGN_ASSUMPTION; Note: R07 concept geometry; dimensions and connections not structurally verified.

# IfcBuildingElementProxy: Limite south · gabião 30 · pedra aparente
In: Lares · Rua das Mercês · artigo 4771
PredefinedType: USERDEFINED; Material: Gabião · pedra irregular
Pset_CasaProvenance - DesignSource: Casa Sobreposta / configuration.json; ReferenceFile: 260617_CasaDFL_Estrutura_Terreno.ifc; ConstructionBasis: DESIGN_ASSUMPTION; Note: R07 concept geometry; dimensions and connections not structurally verified.

# IfcBuildingElementProxy: Limite south · gabião 31 · cesto galvanizado
In: Lares · Rua das Mercês · artigo 4771
PredefinedType: USERDEFINED; Material: Aço galvanizado / Stahl verzinkt
Pset_CasaProvenance - DesignSource: Casa Sobreposta / configuration.json; ReferenceFile: 260617_CasaDFL_Estrutura_Terreno.ifc; ConstructionBasis: DESIGN_ASSUMPTION; Note: R07 concept geometry; dimensions and connections not structurally verified.

# IfcBuildingElementProxy: Limite south · gabião 31 · pedra aparente
In: Lares · Rua das Mercês · artigo 4771
PredefinedType: USERDEFINED; Material: Gabião · pedra irregular
Pset_CasaProvenance - DesignSource: Casa Sobreposta / configuration.json; ReferenceFile: 260617_CasaDFL_Estrutura_Terreno.ifc; ConstructionBasis: DESIGN_ASSUMPTION; Note: R07 concept geometry; dimensions and connections not structurally verified.

# IfcBuildingElementProxy: Limite south · gabião 4 · cesto galvanizado
In: Lares · Rua das Mercês · artigo 4771
PredefinedType: USERDEFINED; Material: Aço galvanizado / Stahl verzinkt
Pset_CasaProvenance - DesignSource: Casa Sobreposta / configuration.json; ReferenceFile: 260617_CasaDFL_Estrutura_Terreno.ifc; ConstructionBasis: DESIGN_ASSUMPTION; Note: R07 concept geometry; dimensions and connections not structurally verified.

# IfcBuildingElementProxy: Limite south · gabião 4 · pedra aparente
In: Lares · Rua das Mercês · artigo 4771
PredefinedType: USERDEFINED; Material: Gabião · pedra irregular
Pset_CasaProvenance - DesignSource: Casa Sobreposta / configuration.json; ReferenceFile: 260617_CasaDFL_Estrutura_Terreno.ifc; ConstructionBasis: DESIGN_ASSUMPTION; Note: R07 concept geometry; dimensions and connections not structurally verified.

# IfcBuildingElementProxy: Limite south · gabião 5 · cesto galvanizado
In: Lares · Rua das Mercês · artigo 4771
PredefinedType: USERDEFINED; Material: Aço galvanizado / Stahl verzinkt
Pset_CasaProvenance - DesignSource: Casa Sobreposta / configuration.json; ReferenceFile: 260617_CasaDFL_Estrutura_Terreno.ifc; ConstructionBasis: DESIGN_ASSUMPTION; Note: R07 concept geometry; dimensions and connections not structurally verified.

# IfcBuildingElementProxy: Limite south · gabião 5 · pedra aparente
In: Lares · Rua das Mercês · artigo 4771
PredefinedType: USERDEFINED; Material: Gabião · pedra irregular
Pset_CasaProvenance - DesignSource: Casa Sobreposta / configuration.json; ReferenceFile: 260617_CasaDFL_Estrutura_Terreno.ifc; ConstructionBasis: DESIGN_ASSUMPTION; Note: R07 concept geometry; dimensions and connections not structurally verified.

# IfcBuildingElementProxy: Limite south · gabião 6 · cesto galvanizado
In: Lares · Rua das Mercês · artigo 4771
PredefinedType: USERDEFINED; Material: Aço galvanizado / Stahl verzinkt
Pset_CasaProvenance - DesignSource: Casa Sobreposta / configuration.json; ReferenceFile: 260617_CasaDFL_Estrutura_Terreno.ifc; ConstructionBasis: DESIGN_ASSUMPTION; Note: R07 concept geometry; dimensions and connections not structurally verified.

# IfcBuildingElementProxy: Limite south · gabião 6 · pedra aparente
In: Lares · Rua das Mercês · artigo 4771
PredefinedType: USERDEFINED; Material: Gabião · pedra irregular
Pset_CasaProvenance - DesignSource: Casa Sobreposta / configuration.json; ReferenceFile: 260617_CasaDFL_Estrutura_Terreno.ifc; ConstructionBasis: DESIGN_ASSUMPTION; Note: R07 concept geometry; dimensions and connections not structurally verified.

# IfcBuildingElementProxy: Limite south · gabião 7 · cesto galvanizado
In: Lares · Rua das Mercês · artigo 4771
PredefinedType: USERDEFINED; Material: Aço galvanizado / Stahl verzinkt
Pset_CasaProvenance - DesignSource: Casa Sobreposta / configuration.json; ReferenceFile: 260617_CasaDFL_Estrutura_Terreno.ifc; ConstructionBasis: DESIGN_ASSUMPTION; Note: R07 concept geometry; dimensions and connections not structurally verified.

# IfcBuildingElementProxy: Limite south · gabião 7 · pedra aparente
In: Lares · Rua das Mercês · artigo 4771
PredefinedType: USERDEFINED; Material: Gabião · pedra irregular
Pset_CasaProvenance - DesignSource: Casa Sobreposta / configuration.json; ReferenceFile: 260617_CasaDFL_Estrutura_Terreno.ifc; ConstructionBasis: DESIGN_ASSUMPTION; Note: R07 concept geometry; dimensions and connections not structurally verified.

# IfcBuildingElementProxy: Limite south · gabião 8 · cesto galvanizado
In: Lares · Rua das Mercês · artigo 4771
PredefinedType: USERDEFINED; Material: Aço galvanizado / Stahl verzinkt
Pset_CasaProvenance - DesignSource: Casa Sobreposta / configuration.json; ReferenceFile: 260617_CasaDFL_Estrutura_Terreno.ifc; ConstructionBasis: DESIGN_ASSUMPTION; Note: R07 concept geometry; dimensions and connections not structurally verified.

# IfcBuildingElementProxy: Limite south · gabião 8 · pedra aparente
In: Lares · Rua das Mercês · artigo 4771
PredefinedType: USERDEFINED; Material: Gabião · pedra irregular
Pset_CasaProvenance - DesignSource: Casa Sobreposta / configuration.json; ReferenceFile: 260617_CasaDFL_Estrutura_Terreno.ifc; ConstructionBasis: DESIGN_ASSUMPTION; Note: R07 concept geometry; dimensions and connections not structurally verified.

# IfcBuildingElementProxy: Limite south · gabião 9 · cesto galvanizado
In: Lares · Rua das Mercês · artigo 4771
PredefinedType: USERDEFINED; Material: Aço galvanizado / Stahl verzinkt
Pset_CasaProvenance - DesignSource: Casa Sobreposta / configuration.json; ReferenceFile: 260617_CasaDFL_Estrutura_Terreno.ifc; ConstructionBasis: DESIGN_ASSUMPTION; Note: R07 concept geometry; dimensions and connections not structurally verified.

# IfcBuildingElementProxy: Limite south · gabião 9 · pedra aparente
In: Lares · Rua das Mercês · artigo 4771
PredefinedType: USERDEFINED; Material: Gabião · pedra irregular
Pset_CasaProvenance - DesignSource: Casa Sobreposta / configuration.json; ReferenceFile: 260617_CasaDFL_Estrutura_Terreno.ifc; ConstructionBasis: DESIGN_ASSUMPTION; Note: R07 concept geometry; dimensions and connections not structurally verified.

# IfcBuildingElementProxy: Limite south · vala de interceção (46)
In: Lares · Rua das Mercês · artigo 4771
PredefinedType: USERDEFINED; Material: Brita drenante
Pset_CasaProvenance - DesignSource: Casa Sobreposta / configuration.json; ReferenceFile: 260617_CasaDFL_Estrutura_Terreno.ifc; ConstructionBasis: DESIGN_ASSUMPTION

# IfcBuildingElementProxy: Trepadeiras · floreira (10)
In: 00 · Habitação e estacionamento
PredefinedType: USERDEFINED; Material: Betão armado / Stahlbeton
Pset_CasaProvenance - DesignSource: Casa Sobreposta / configuration.json; ReferenceFile: 260617_CasaDFL_Estrutura_Terreno.ifc; ConstructionBasis: DESIGN_ASSUMPTION; Note: Indicative planter; soil volume, irrigation, root space and waterproofing to design.

# IfcColumn (55)
Material: Betão armado / Stahlbeton
Pset_CasaProvenance - DesignSource: Casa Sobreposta / configuration.json; ReferenceFile: 260617_CasaDFL_Estrutura_Terreno.ifc
Name | In | ConstructionBasis
Pedestal 1A · betão 400 x 400 | 00 · Habitação e estacionamento | ADAPTED_REFERENCE
Pedestal 1B · betão 400 x 400 | 00 · Habitação e estacionamento | ADAPTED_REFERENCE
Pedestal 2A · betão 400 x 400 | 00 · Habitação e estacionamento | ADAPTED_REFERENCE
Pedestal 2B · betão 400 x 400 | 00 · Habitação e estacionamento | ADAPTED_REFERENCE
Pedestal 3A · betão 400 x 400 | 00 · Habitação e estacionamento | ADAPTED_REFERENCE
Pedestal 3B · betão 400 x 400 | 00 · Habitação e estacionamento | ADAPTED_REFERENCE
Pedestal 4A · betão 400 x 400 | 00 · Habitação e estacionamento | ADAPTED_REFERENCE
Pedestal 4B · betão 400 x 400 | 00 · Habitação e estacionamento | ADAPTED_REFERENCE
Pedestal 5A · betão 400 x 400 | 00 · Habitação e estacionamento | ADAPTED_REFERENCE
Pedestal 5B · betão 400 x 400 | 00 · Habitação e estacionamento | ADAPTED_REFERENCE
Pedestal 6A · betão 400 x 400 | 00 · Habitação e estacionamento | ADAPTED_REFERENCE
Pedestal 6B · betão 400 x 400 | 00 · Habitação e estacionamento | ADAPTED_REFERENCE
Pedestal 7A · betão 400 x 400 | 00 · Habitação e estacionamento | ADAPTED_REFERENCE
Pedestal 7B · betão 400 x 400 | 00 · Habitação e estacionamento | ADAPTED_REFERENCE
Pedestal 8A · betão 400 x 400 | 00 · Habitação e estacionamento | ADAPTED_REFERENCE
Pedestal 8B · betão 400 x 400 | 00 · Habitação e estacionamento | ADAPTED_REFERENCE
33 x Pódio suspenso · apoio sobre o terreno | 00 · Habitação e estacionamento | DESIGN_ASSUMPTION
6 x Acesso · apoio do tabuleiro | Lares · Rua das Mercês · artigo 4771 | DESIGN_ASSUMPTION

# IfcColumn: IPE240 / steel (46)
Type - Material: Aço pintado / Stahl lackiert
Pset_CasaProvenance - DesignSource: Casa Sobreposta / configuration.json; ReferenceFile: 260617_CasaDFL_Estrutura_Terreno.ifc; ConstructionBasis: ADAPTED_REFERENCE; Note: Reference section; spans, stability and connections require design.
Name | In
Pilar 1A · IPE240 | 00 · Habitação e estacionamento
Pilar estufa 1A · IPE240 | 01 · Jardim de inverno
Pilar 1B · IPE240 | 00 · Habitação e estacionamento
Pilar estufa 1B · IPE240 | 01 · Jardim de inverno
Pilar 2A · IPE240 | 00 · Habitação e estacionamento
Pilar estufa 2A · IPE240 | 01 · Jardim de inverno
Pilar 2B · IPE240 | 00 · Habitação e estacionamento
Pilar estufa 2B · IPE240 | 01 · Jardim de inverno
Pilar 3A · IPE240 | 00 · Habitação e estacionamento
Pilar estufa 3A · IPE240 | 01 · Jardim de inverno
Pilar 3B · IPE240 | 00 · Habitação e estacionamento
Pilar estufa 3B · IPE240 | 01 · Jardim de inverno
Pilar 4A · IPE240 | 00 · Habitação e estacionamento
Pilar estufa 4A · IPE240 | 01 · Jardim de inverno
Pilar 4B · IPE240 | 00 · Habitação e estacionamento
Pilar estufa 4B · IPE240 | 01 · Jardim de inverno
Pilar 5A · IPE240 | 00 · Habitação e estacionamento
Pilar estufa 5A · IPE240 | 01 · Jardim de inverno
Pilar 5B · IPE240 | 00 · Habitação e estacionamento
Pilar estufa 5B · IPE240 | 01 · Jardim de inverno
Pilar 6A · IPE240 | 00 · Habitação e estacionamento
Pilar estufa 6A · IPE240 | 01 · Jardim de inverno
Pilar 6B · IPE240 | 00 · Habitação e estacionamento
Pilar estufa 6B · IPE240 | 01 · Jardim de inverno
Pilar 7A · IPE240 | 00 · Habitação e estacionamento
Pilar estufa 7A · IPE240 | 01 · Jardim de inverno
Pilar 7B · IPE240 | 00 · Habitação e estacionamento
Pilar estufa 7B · IPE240 | 01 · Jardim de inverno
Pilar 8A · IPE240 | 00 · Habitação e estacionamento
Pilar estufa 8A · IPE240 | 01 · Jardim de inverno
Pilar 8B · IPE240 | 00 · Habitação e estacionamento
Pilar estufa 8B · IPE240 | 01 · Jardim de inverno
4 x Pérgola · pilar de duplo pé-direito | 00 · Habitação e estacionamento
9 x Projeção estufa · pilar sul ao pódio | 00 · Habitação e estacionamento
Projeção estufa · pilar nascente norte | 00 · Habitação e estacionamento

# IfcColumn: RHS80x60x4 / steel (4)
In: 00 · Habitação e estacionamento
Type - Material: Aço pintado / Stahl lackiert
Pset_CasaProvenance - DesignSource: Casa Sobreposta / configuration.json; ReferenceFile: 260617_CasaDFL_Estrutura_Terreno.ifc; ConstructionBasis: DESIGN_ASSUMPTION; Note: Reference section; spans, stability and connections require design.

# IfcCovering (9)
Pset_CasaProvenance - DesignSource: Casa Sobreposta / configuration.json; ReferenceFile: 260617_CasaDFL_Estrutura_Terreno.ifc; ConstructionBasis: DESIGN_ASSUMPTION
Name | In | PredefinedType | Material
Impermeabilização da estufa · hipótese | 01 · Jardim de inverno | FLOORING | Membrana impermeável — hipótese | Pset_CasaProvenance - Note: Two real stair voids. Light protective finish assumed; drains and waterproof upstands require detailing.
Proteção do pavimento · hipótese | 01 · Jardim de inverno | FLOORING | Pavimento protetor leve — hipótese | Pset_CasaProvenance - Note: Two real stair voids. Light protective finish assumed; drains and waterproof upstands require detailing.
Teto caixa térmica 1 | 01 · Jardim de inverno | CEILING | Pavimento protetor leve — hipótese
Teto caixa térmica 2 | 01 · Jardim de inverno | CEILING | Pavimento protetor leve — hipótese
Cisterna · camada drenante 100 mm | -01 · Cisterna sob o terraço | FLOORING | Brita drenante
Cisterna · impermeabilização poente | -01 · Cisterna sob o terraço | MEMBRANE | Membrana impermeável — hipótese
Cisterna · impermeabilização norte | -01 · Cisterna sob o terraço | MEMBRANE | Membrana impermeável — hipótese
Cisterna · impermeabilização sul | -01 · Cisterna sob o terraço | MEMBRANE | Membrana impermeável — hipótese
Cisterna · impermeabilização nascente | -01 · Cisterna sob o terraço | MEMBRANE | Membrana impermeável — hipótese

# IfcCovering: Cortina interior · 75% (9)
In: 01 · Jardim de inverno
PredefinedType: USERDEFINED; Material: Tecido de sombreamento — hipótese
Pset_CasaProvenance - DesignSource: Casa Sobreposta / configuration.json; ReferenceFile: 260617_CasaDFL_Estrutura_Terreno.ifc; ConstructionBasis: DESIGN_ASSUMPTION; Note: 75% deployment snapshot; fabric specification and cables not sized.

# IfcCovering: Pátio · sombreador têxtil retrátil (2)
In: 00 · Habitação e estacionamento
PredefinedType: USERDEFINED; Material: Tecido de sombreamento — hipótese
Pset_CasaProvenance - DesignSource: Casa Sobreposta / configuration.json; ReferenceFile: 260617_CasaDFL_Estrutura_Terreno.ifc; ConstructionBasis: DESIGN_ASSUMPTION; Note: Same fabric intent as internal shades, shown partially deployed. No wind-speed rating; retraction does not prove storm safety.

# IfcDoor (22)
PredefinedType: DOOR
Pset_CasaProvenance - DesignSource: Casa Sobreposta / configuration.json; ReferenceFile: 260617_CasaDFL_Estrutura_Terreno.ifc
Name | In | OverallHeight (m) | OverallWidth (m) | OperationType | Material | ConstructionBasis
Porta interior 1 | 00 · Habitação e estacionamento | 2.1 | 0.830093 | SINGLE_SWING_LEFT | OSB | ADAPTED_REFERENCE
Porta interior 2 | 00 · Habitação e estacionamento | 2.1 | 0.830093 | SINGLE_SWING_LEFT | OSB | ADAPTED_REFERENCE
Porta interior 3 | 00 · Habitação e estacionamento | 2.1 | 0.730086 | SINGLE_SWING_LEFT | OSB | ADAPTED_REFERENCE
Porta interior 4 | 00 · Habitação e estacionamento | 2.1 | 0.830092 | SINGLE_SWING_LEFT | OSB | ADAPTED_REFERENCE
Porta interior 5 | 00 · Habitação e estacionamento | 2.1 | 0.830077 | SINGLE_SWING_LEFT | OSB | ADAPTED_REFERENCE
Porta interior 6 | 00 · Habitação e estacionamento | 2.1 | 0.730017 | SINGLE_SWING_LEFT | OSB | ADAPTED_REFERENCE
Porta do estacionamento | 00 · Habitação e estacionamento | 2.1 | 0.83 | SINGLE_SWING_LEFT | Aço pintado / Stahl lackiert | ADAPTED_REFERENCE
Folha de correr sul 2 | 00 · Habitação e estacionamento | 2.918 | 1.97133 | SLIDING_TO_LEFT | Vidro / Normalglas | DESIGN_ASSUMPTION
Folha de correr sul 4 | 00 · Habitação e estacionamento | 2.918 | 1.97133 | SLIDING_TO_LEFT | Vidro / Normalglas | DESIGN_ASSUMPTION
Folha de correr sul 6 | 00 · Habitação e estacionamento | 2.918 | 1.97133 | SLIDING_TO_LEFT | Vidro / Normalglas | DESIGN_ASSUMPTION
Folha de correr sul 8 | 00 · Habitação e estacionamento | 2.918 | 1.97133 | SLIDING_TO_LEFT | Vidro / Normalglas | DESIGN_ASSUMPTION
Folha de correr sul 10 | 00 · Habitação e estacionamento | 2.918 | 1.97133 | SLIDING_TO_LEFT | Vidro / Normalglas | DESIGN_ASSUMPTION
Folha de correr sul 12 | 00 · Habitação e estacionamento | 2.918 | 0.614 | SLIDING_TO_LEFT | Vidro / Normalglas | DESIGN_ASSUMPTION
Fachada poente integralmente envidraçada · módulo 4 | 00 · Habitação e estacionamento | 2.918 | 1.55 | SLIDING_TO_LEFT | Vidro / Normalglas | DESIGN_ASSUMPTION | Pset_CasaGlazedFacade - Revision: R02 · kiwi pergola; Facade: WEST / highlighted end in user sketch; Infill: Full-height glazing; no opaque infill; GlazingSpecification: 8 mm nominal representation only; insulated safety glazing assembly to specify
Porta banho superior | 01 · Jardim de inverno | 2.1 | 0.8 | SINGLE_SWING_LEFT | OSB | ADAPTED_REFERENCE
Varanda · porta de correr oeste | 01 · Jardim de inverno | 2.15 | 1.05 | SLIDING_TO_LEFT | Vidro / Normalglas | DESIGN_ASSUMPTION
Caixa térmica 1 · north | 01 · Jardim de inverno | 2.15 | 0.9 | SLIDING_TO_LEFT | Vidro / Normalglas | DESIGN_ASSUMPTION
Caixa térmica 2 · south | 01 · Jardim de inverno | 2.15 | 0.91 | SLIDING_TO_LEFT | Vidro / Normalglas | DESIGN_ASSUMPTION
2 x Contentor · porta dupla | 00 · Habitação e estacionamento | 2.39 | 1.17 | SINGLE_SWING_LEFT | Contentor · pintura 1 | DESIGN_ASSUMPTION
2 x Contentor · porta dupla | 00 · Habitação e estacionamento | 2.39 | 1.17 | SINGLE_SWING_LEFT | Contentor · pintura 2 | DESIGN_ASSUMPTION

# IfcElementAssembly: Acesso · guarda lateral do troço suspenso (6)
In: Lares · Rua das Mercês · artigo 4771
PredefinedType: USERDEFINED
Pset_CasaProvenance - DesignSource: Casa Sobreposta / configuration.json; ReferenceFile: 260617_CasaDFL_Estrutura_Terreno.ifc; ConstructionBasis: DESIGN_ASSUMPTION

# IfcElementAssembly: CISTERN_PODIUM, Pódio · terraço, casa térrea e cisterna
In: 00 · Habitação e estacionamento
PredefinedType: USERDEFINED
Pset_CasaProvenance - DesignSource: Casa Sobreposta / configuration.json; ReferenceFile: 260617_CasaDFL_Estrutura_Terreno.ifc; ConstructionBasis: DESIGN_ASSUMPTION
Pset_CasaUndercroft - NaturalGroundRetained: yes; EnclosedStorage: no; Use: Open ventilated sloping void; not a habitable or storage storey; StructuralStatus: Concept slab, beams, piers and foundation sizes; geotechnical and structural design pending
Pset_CasaPodium - TankGrossPlan_m2: 23; TankBaseLevel_m: 13.2; MinimumInternalHeight_m: 2.31; FloorSupport: Entire podium suspended on discrete supports above natural slope; PlanningAssumption: Cistern excluded from 250 m2 by explicit user confirmation 2026-10-02

# IfcElementAssembly: EXISTING_SHIPPING_CONTAINER (2)
In: 00 · Habitação e estacionamento
PredefinedType: USERDEFINED
Pset_CasaProvenance - DesignSource: Casa Sobreposta / configuration.json; ReferenceFile: 260617_CasaDFL_Estrutura_Terreno.ifc; ConstructionBasis: DESIGN_ASSUMPTION
Pset_CasaExistingContext - Length_m: 6; WidthAssumed_m: 2.44; HeightAssumed_m: 2.59; Location: Digitised visible roofs from signed orthophoto; fitted 6 x 2.44 m, provisional +/- 0.50 m, verify ground corners; Status: Existing context; not included in new building setback or new floor-area schedule; Colour: Illustrative, condition not surveyed
Name
Contentor existente 1 · 6 m
Contentor existente 2 · 6 m

# IfcElementAssembly: LIVING_SHADE_TRELLIS, Fachada sul e pátio · estrutura e trepadeiras
In: 00 · Habitação e estacionamento
PredefinedType: USERDEFINED
Pset_CasaProvenance - DesignSource: Casa Sobreposta / configuration.json; ReferenceFile: 260617_CasaDFL_Estrutura_Terreno.ifc; ConstructionBasis: DESIGN_ASSUMPTION

# IfcElementAssembly: PERGOLA_GREENHOUSE_EXTENSION, Pérgola · prolongamento da estufa 6 m
In: 00 · Habitação e estacionamento
PredefinedType: USERDEFINED
Pset_CasaProvenance - DesignSource: Casa Sobreposta / configuration.json; ReferenceFile: 260617_CasaDFL_Estrutura_Terreno.ifc; ConstructionBasis: DESIGN_ASSUMPTION
Pset_CasaVeranda - ClearWidth_m: 1.2; GrossArea_m2: 9.875; PlanningStatus: Counted conservatively in 250 m2 budget; municipal classification unconfirmed
Pset_CasaPergola - Projection_m: 6; Frontage_m: 7.9; OpenCanopyArea_m2: 47.4; EavesRelativeHeight_m: 6.22; Roof: Open extension of greenhouse curved profile, no glass enclosure; StructuralStatus: Gravity and lateral load path indicated; no wind-speed rating or member/anchor verification

# IfcFooting (71)
Material: Betão armado / Stahlbeton
Pset_CasaProvenance - DesignSource: Casa Sobreposta / configuration.json; ReferenceFile: 260617_CasaDFL_Estrutura_Terreno.ifc
Name | In | PredefinedType | ConstructionBasis
Sapata 1A · hipótese | 00 · Habitação e estacionamento | PAD_FOOTING | ADAPTED_REFERENCE | Pset_CasaProvenance - Note: 1.20 x 1.20 x 0.35 m assumed pad; R03 steps below original ground where survey is available. Bearing, settlement and reinforcement unverified.
Sapata 1B · hipótese | 00 · Habitação e estacionamento | PAD_FOOTING | ADAPTED_REFERENCE | Pset_CasaProvenance - Note: 1.20 x 1.20 x 0.35 m assumed pad; R03 steps below original ground where survey is available. Bearing, settlement and reinforcement unverified.
Sapata 2A · hipótese | 00 · Habitação e estacionamento | PAD_FOOTING | ADAPTED_REFERENCE | Pset_CasaProvenance - Note: 1.20 x 1.20 x 0.35 m assumed pad; R03 steps below original ground where survey is available. Bearing, settlement and reinforcement unverified.
Sapata 2B · hipótese | 00 · Habitação e estacionamento | PAD_FOOTING | ADAPTED_REFERENCE | Pset_CasaProvenance - Note: 1.20 x 1.20 x 0.35 m assumed pad; R03 steps below original ground where survey is available. Bearing, settlement and reinforcement unverified.
Sapata 3A · hipótese | 00 · Habitação e estacionamento | PAD_FOOTING | ADAPTED_REFERENCE | Pset_CasaProvenance - Note: 1.20 x 1.20 x 0.35 m assumed pad; R03 steps below original ground where survey is available. Bearing, settlement and reinforcement unverified.
Sapata 3B · hipótese | 00 · Habitação e estacionamento | PAD_FOOTING | ADAPTED_REFERENCE | Pset_CasaProvenance - Note: 1.20 x 1.20 x 0.35 m assumed pad; R03 steps below original ground where survey is available. Bearing, settlement and reinforcement unverified.
Sapata 4A · hipótese | 00 · Habitação e estacionamento | PAD_FOOTING | ADAPTED_REFERENCE | Pset_CasaProvenance - Note: 1.20 x 1.20 x 0.35 m assumed pad; R03 steps below original ground where survey is available. Bearing, settlement and reinforcement unverified.
Sapata 4B · hipótese | 00 · Habitação e estacionamento | PAD_FOOTING | ADAPTED_REFERENCE | Pset_CasaProvenance - Note: 1.20 x 1.20 x 0.35 m assumed pad; R03 steps below original ground where survey is available. Bearing, settlement and reinforcement unverified.
Sapata 5A · hipótese | 00 · Habitação e estacionamento | PAD_FOOTING | ADAPTED_REFERENCE | Pset_CasaProvenance - Note: 1.20 x 1.20 x 0.35 m assumed pad; R03 steps below original ground where survey is available. Bearing, settlement and reinforcement unverified.
Sapata 5B · hipótese | 00 · Habitação e estacionamento | PAD_FOOTING | ADAPTED_REFERENCE | Pset_CasaProvenance - Note: 1.20 x 1.20 x 0.35 m assumed pad; R03 steps below original ground where survey is available. Bearing, settlement and reinforcement unverified.
Sapata 6A · hipótese | 00 · Habitação e estacionamento | PAD_FOOTING | ADAPTED_REFERENCE | Pset_CasaProvenance - Note: 1.20 x 1.20 x 0.35 m assumed pad; R03 steps below original ground where survey is available. Bearing, settlement and reinforcement unverified.
Sapata 6B · hipótese | 00 · Habitação e estacionamento | PAD_FOOTING | ADAPTED_REFERENCE | Pset_CasaProvenance - Note: 1.20 x 1.20 x 0.35 m assumed pad; R03 steps below original ground where survey is available. Bearing, settlement and reinforcement unverified.
Sapata 7A · hipótese | 00 · Habitação e estacionamento | PAD_FOOTING | ADAPTED_REFERENCE | Pset_CasaProvenance - Note: 1.20 x 1.20 x 0.35 m assumed pad; R03 steps below original ground where survey is available. Bearing, settlement and reinforcement unverified.
Sapata 7B · hipótese | 00 · Habitação e estacionamento | PAD_FOOTING | ADAPTED_REFERENCE | Pset_CasaProvenance - Note: 1.20 x 1.20 x 0.35 m assumed pad; R03 steps below original ground where survey is available. Bearing, settlement and reinforcement unverified.
Sapata 8A · hipótese | 00 · Habitação e estacionamento | PAD_FOOTING | ADAPTED_REFERENCE | Pset_CasaProvenance - Note: 1.20 x 1.20 x 0.35 m assumed pad; R03 steps below original ground where survey is available. Bearing, settlement and reinforcement unverified.
Sapata 8B · hipótese | 00 · Habitação e estacionamento | PAD_FOOTING | ADAPTED_REFERENCE | Pset_CasaProvenance - Note: 1.20 x 1.20 x 0.35 m assumed pad; R03 steps below original ground where survey is available. Bearing, settlement and reinforcement unverified.
Cisterna · sapata corrida poente | -01 · Cisterna sob o terraço | STRIP_FOOTING | DESIGN_ASSUMPTION
Cisterna · sapata corrida norte | -01 · Cisterna sob o terraço | STRIP_FOOTING | DESIGN_ASSUMPTION
Cisterna · sapata corrida sul | -01 · Cisterna sob o terraço | STRIP_FOOTING | DESIGN_ASSUMPTION
Cisterna · sapata corrida nascente | -01 · Cisterna sob o terraço | STRIP_FOOTING | DESIGN_ASSUMPTION
4 x Jardim · apoio | 00 · Habitação e estacionamento | PAD_FOOTING | DESIGN_ASSUMPTION
33 x Pódio suspenso · sapata pontual | 00 · Habitação e estacionamento | PAD_FOOTING | DESIGN_ASSUMPTION
8 x Contentor · apoio existente indicativo | 00 · Habitação e estacionamento | PAD_FOOTING | DESIGN_ASSUMPTION
6 x Acesso · sapata pontual | Lares · Rua das Mercês · artigo 4771 | PAD_FOOTING | DESIGN_ASSUMPTION

# IfcFurnishingElement, Ilha da cozinha · esquema
In: 00 · Habitação e estacionamento
Material: OSB
Pset_CasaProvenance - DesignSource: Casa Sobreposta / configuration.json; ReferenceFile: 260617_CasaDFL_Estrutura_Terreno.ifc; ConstructionBasis: ADAPTED_REFERENCE

# IfcGeographicElement, Terreno · R07 com telha, cisterna e drenagem
In: Lares · Rua das Mercês · artigo 4771
PredefinedType: TERRAIN; Material: Terreno · modelação proposta
Pset_CasaProvenance - DesignSource: Casa Sobreposta / configuration.json; ReferenceFile: 260617_CasaDFL_Estrutura_Terreno.ifc; ConstructionBasis: DESIGN_ASSUMPTION

# IfcGeographicElement: ANALYTICAL_CUT_VOLUME, Escavação · diferença entre terrenos
In: Lares · Rua das Mercês · artigo 4771
PredefinedType: USERDEFINED; Material: Escavação · volume analítico
Pset_CasaProvenance - DesignSource: Casa Sobreposta / configuration.json; ReferenceFile: 260617_CasaDFL_Estrutura_Terreno.ifc; ConstructionBasis: DESIGN_ASSUMPTION; Note: ANALYTICAL VOLUME, not additional constructed material. Closed wedges between surveyed and proposed TIN, split where sign changes. Excludes stripping, foundations, services and bulking.
Pset_CasaEarthworks - Kind: CUT; Volume_m3: 45.8495; Method: Exact signed integration of linear proposed/existing display TIN, splitting zero crossings; Excluded: Topsoil stripping, foundation/service trenches, soil replacement, bulking and shrinkage; Status: CONCEPT_GEOMETRIC_VOLUME; not a measured bill of works; DefaultVisibility: Hide analytical volumes in normal model views
Qto_CasaEarthworks - NetVolume: 45.8495 m3

# IfcGeographicElement: ANALYTICAL_FILL_VOLUME, Aterro · diferença entre terrenos
In: Lares · Rua das Mercês · artigo 4771
PredefinedType: USERDEFINED; Material: Aterro · volume analítico
Pset_CasaProvenance - DesignSource: Casa Sobreposta / configuration.json; ReferenceFile: 260617_CasaDFL_Estrutura_Terreno.ifc; ConstructionBasis: DESIGN_ASSUMPTION; Note: ANALYTICAL VOLUME, not additional constructed material. Closed wedges between surveyed and proposed TIN, split where sign changes. Excludes stripping, foundations, services and bulking.
Pset_CasaEarthworks - Kind: FILL; Volume_m3: 34.1829; Method: Exact signed integration of linear proposed/existing display TIN, splitting zero crossings; Excluded: Topsoil stripping, foundation/service trenches, soil replacement, bulking and shrinkage; Status: CONCEPT_GEOMETRIC_VOLUME; not a measured bill of works; DefaultVisibility: Hide analytical volumes in normal model views
Qto_CasaEarthworks - NetVolume: 34.1829 m3

# IfcGeographicElement: Acesso trapezoidal · 8,60 m no pódio / 5,00 m na rua
In: Lares · Rua das Mercês · artigo 4771
PredefinedType: USERDEFINED; Material: Pavimento rugoso · betão vassourado
Pset_CasaProvenance - DesignSource: Casa Sobreposta / configuration.json; ReferenceFile: 260617_CasaDFL_Estrutura_Terreno.ifc; ConstructionBasis: DESIGN_ASSUMPTION

# IfcGeographicElement: Marcação no solo · árvore indicativa 01
In: Lares · Rua das Mercês · artigo 4771
PredefinedType: USERDEFINED; Material: Marcação de plantação · linha no terreno
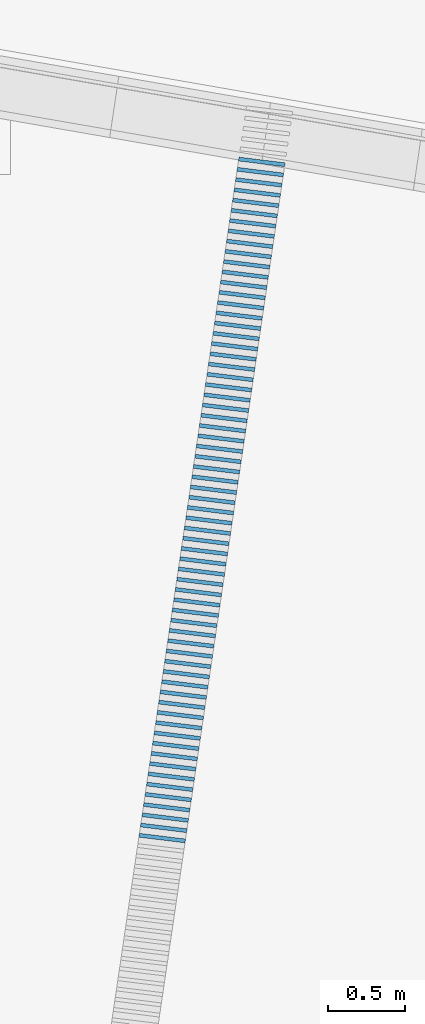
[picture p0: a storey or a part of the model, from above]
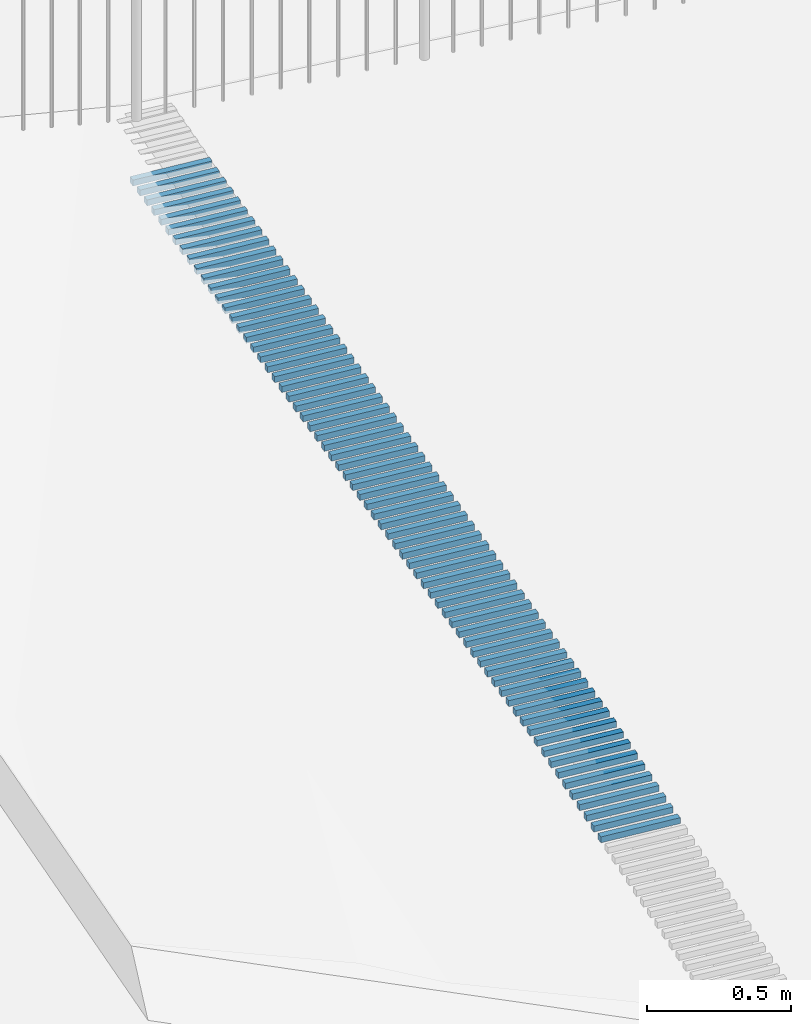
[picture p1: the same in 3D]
Properties of the parts of a building model (IFC4), part 4 of 4

# IfcWall (17)
Name | In | Material | OverallThickness_m | SourceModelSkinThicknesses_m | Core_m | Pset_CasaAssembly, Note
Painel opaco sul 5 | 00 · Habitação e estacionamento | Aço pintado / Stahl lackiert 0.005 m, Lã mineral / Mineralwolle 2 0.12 m, Aço pintado / Stahl lackiert 0.00516 m | 0.13016 | 0.005 / 0.00516 | 0.12 | Source geometry retained; commercial sheet specification not established.
Painel opaco sul 7 | 00 · Habitação e estacionamento | Aço pintado / Stahl lackiert 0.005 m, Lã mineral / Mineralwolle 2 0.12 m, Aço pintado / Stahl lackiert 0.00516 m | 0.13016 | 0.005 / 0.00516 | 0.12 | Source geometry retained; commercial sheet specification not established.
Painel opaco sul 9 | 00 · Habitação e estacionamento | Aço pintado / Stahl lackiert 0.005 m, Lã mineral / Mineralwolle 2 0.12 m, Aço pintado / Stahl lackiert 0.00516 m | 0.13016 | 0.005 / 0.00516 | 0.12 | Source geometry retained; commercial sheet specification not established.
Painel opaco sul 11 | 00 · Habitação e estacionamento | Aço pintado / Stahl lackiert 0.005 m, Lã mineral / Mineralwolle 2 0.12 m, Aço pintado / Stahl lackiert 0.00516 m | 0.13016 | 0.005 / 0.00516 | 0.12 | Source geometry retained; commercial sheet specification not established.
Banho superior · poente | 01 · Jardim de inverno | OSB
Banho superior · norte | 01 · Jardim de inverno | OSB
Banho superior · nascente | 01 · Jardim de inverno | OSB
Banho superior · sul | 01 · Jardim de inverno | OSB

# IfcWall: Acesso · gabião -1 12.0 · núcleo de pedra
In: Lares · Rua das Mercês · artigo 4771
PredefinedType: USERDEFINED; Material: Gabião · enchimento
Pset_CasaProvenance - DesignSource: Casa Sobreposta / configuration.json; ReferenceFile: 260617_CasaDFL_Estrutura_Terreno.ifc; ConstructionBasis: DESIGN_ASSUMPTION; Note: Concept gabion envelope; mesh gauge, foundation, filter and retaining capacity to design.
Pset_CasaBoundary - BaseSurveyLevel_m: 14.3333; TopSurveyLevel_m: 15.733; Status: CONCEPT_NOT_SIZED

# IfcWall: Acesso · gabião -1 15.0 · núcleo de pedra
In: Lares · Rua das Mercês · artigo 4771
PredefinedType: USERDEFINED; Material: Gabião · enchimento
Pset_CasaProvenance - DesignSource: Casa Sobreposta / configuration.json; ReferenceFile: 260617_CasaDFL_Estrutura_Terreno.ifc; ConstructionBasis: DESIGN_ASSUMPTION; Note: Concept gabion envelope; mesh gauge, foundation, filter and retaining capacity to design.
Pset_CasaBoundary - BaseSurveyLevel_m: 14.5072; TopSurveyLevel_m: 15.736; Status: CONCEPT_NOT_SIZED

# IfcWall: Acesso · gabião -1 18.0 · núcleo de pedra
In: Lares · Rua das Mercês · artigo 4771
PredefinedType: USERDEFINED; Material: Gabião · enchimento
Pset_CasaProvenance - DesignSource: Casa Sobreposta / configuration.json; ReferenceFile: 260617_CasaDFL_Estrutura_Terreno.ifc; ConstructionBasis: DESIGN_ASSUMPTION; Note: Concept gabion envelope; mesh gauge, foundation, filter and retaining capacity to design.
Pset_CasaBoundary - BaseSurveyLevel_m: 14.6824; TopSurveyLevel_m: 15.739; Status: CONCEPT_NOT_SIZED

# IfcWall: Acesso · gabião -1 21.0 · núcleo de pedra
In: Lares · Rua das Mercês · artigo 4771
PredefinedType: USERDEFINED; Material: Gabião · enchimento
Pset_CasaProvenance - DesignSource: Casa Sobreposta / configuration.json; ReferenceFile: 260617_CasaDFL_Estrutura_Terreno.ifc; ConstructionBasis: DESIGN_ASSUMPTION; Note: Concept gabion envelope; mesh gauge, foundation, filter and retaining capacity to design.
Pset_CasaBoundary - BaseSurveyLevel_m: 14.8576; TopSurveyLevel_m: 15.8609; Status: CONCEPT_NOT_SIZED

# IfcWall: Acesso · gabião -1 24.0 · núcleo de pedra
In: Lares · Rua das Mercês · artigo 4771
PredefinedType: USERDEFINED; Material: Gabião · enchimento
Pset_CasaProvenance - DesignSource: Casa Sobreposta / configuration.json; ReferenceFile: 260617_CasaDFL_Estrutura_Terreno.ifc; ConstructionBasis: DESIGN_ASSUMPTION; Note: Concept gabion envelope; mesh gauge, foundation, filter and retaining capacity to design.
Pset_CasaBoundary - BaseSurveyLevel_m: 15.0114; TopSurveyLevel_m: 16.0133; Status: CONCEPT_NOT_SIZED

# IfcWall: Acesso · gabião -1 27.0 · núcleo de pedra
In: Lares · Rua das Mercês · artigo 4771
PredefinedType: USERDEFINED; Material: Gabião · enchimento
Pset_CasaProvenance - DesignSource: Casa Sobreposta / configuration.json; ReferenceFile: 260617_CasaDFL_Estrutura_Terreno.ifc; ConstructionBasis: DESIGN_ASSUMPTION; Note: Concept gabion envelope; mesh gauge, foundation, filter and retaining capacity to design.
Pset_CasaBoundary - BaseSurveyLevel_m: 15.2016; TopSurveyLevel_m: 16.1742; Status: CONCEPT_NOT_SIZED

# IfcWall: Acesso · gabião -1 30.0 · núcleo de pedra
In: Lares · Rua das Mercês · artigo 4771
PredefinedType: USERDEFINED; Material: Gabião · enchimento
Pset_CasaProvenance - DesignSource: Casa Sobreposta / configuration.json; ReferenceFile: 260617_CasaDFL_Estrutura_Terreno.ifc; ConstructionBasis: DESIGN_ASSUMPTION; Note: Concept gabion envelope; mesh gauge, foundation, filter and retaining capacity to design.
Pset_CasaBoundary - BaseSurveyLevel_m: 15.3761; TopSurveyLevel_m: 16.2987; Status: CONCEPT_NOT_SIZED

# IfcWall: Acesso · gabião -1 33.0 · núcleo de pedra
In: Lares · Rua das Mercês · artigo 4771
PredefinedType: USERDEFINED; Material: Gabião · enchimento
Pset_CasaProvenance - DesignSource: Casa Sobreposta / configuration.json; ReferenceFile: 260617_CasaDFL_Estrutura_Terreno.ifc; ConstructionBasis: DESIGN_ASSUMPTION; Note: Concept gabion envelope; mesh gauge, foundation, filter and retaining capacity to design.
Pset_CasaBoundary - BaseSurveyLevel_m: 15.5502; TopSurveyLevel_m: 16.3676; Status: CONCEPT_NOT_SIZED

# IfcWall: Acesso · gabião -1 9.0 · núcleo de pedra
In: Lares · Rua das Mercês · artigo 4771
PredefinedType: USERDEFINED; Material: Gabião · enchimento
Pset_CasaProvenance - DesignSource: Casa Sobreposta / configuration.json; ReferenceFile: 260617_CasaDFL_Estrutura_Terreno.ifc; ConstructionBasis: DESIGN_ASSUMPTION; Note: Concept gabion envelope; mesh gauge, foundation, filter and retaining capacity to design.
Pset_CasaBoundary - BaseSurveyLevel_m: 14.2084; TopSurveyLevel_m: 15.73; Status: CONCEPT_NOT_SIZED

# IfcWall: Acesso · gabião 1 12.0 · núcleo de pedra
In: Lares · Rua das Mercês · artigo 4771
PredefinedType: USERDEFINED; Material: Gabião · enchimento
Pset_CasaProvenance - DesignSource: Casa Sobreposta / configuration.json; ReferenceFile: 260617_CasaDFL_Estrutura_Terreno.ifc; ConstructionBasis: DESIGN_ASSUMPTION; Note: Concept gabion envelope; mesh gauge, foundation, filter and retaining capacity to design.
Pset_CasaBoundary - BaseSurveyLevel_m: 14.8446; TopSurveyLevel_m: 15.733; Status: CONCEPT_NOT_SIZED

# IfcWall: Acesso · gabião 1 15.0 · núcleo de pedra
In: Lares · Rua das Mercês · artigo 4771
PredefinedType: USERDEFINED; Material: Gabião · enchimento
Pset_CasaProvenance - DesignSource: Casa Sobreposta / configuration.json; ReferenceFile: 260617_CasaDFL_Estrutura_Terreno.ifc; ConstructionBasis: DESIGN_ASSUMPTION; Note: Concept gabion envelope; mesh gauge, foundation, filter and retaining capacity to design.
Pset_CasaBoundary - BaseSurveyLevel_m: 15.0671; TopSurveyLevel_m: 15.7374; Status: CONCEPT_NOT_SIZED

# IfcWall: Acesso · gabião 1 18.0 · núcleo de pedra
In: Lares · Rua das Mercês · artigo 4771
PredefinedType: USERDEFINED; Material: Gabião · enchimento
Pset_CasaProvenance - DesignSource: Casa Sobreposta / configuration.json; ReferenceFile: 260617_CasaDFL_Estrutura_Terreno.ifc; ConstructionBasis: DESIGN_ASSUMPTION; Note: Concept gabion envelope; mesh gauge, foundation, filter and retaining capacity to design.
Pset_CasaBoundary - BaseSurveyLevel_m: 15.266; TopSurveyLevel_m: 15.8642; Status: CONCEPT_NOT_SIZED

# IfcWall: Acesso · gabião 1 21.0 · núcleo de pedra
In: Lares · Rua das Mercês · artigo 4771
PredefinedType: USERDEFINED; Material: Gabião · enchimento
Pset_CasaProvenance - DesignSource: Casa Sobreposta / configuration.json; ReferenceFile: 260617_CasaDFL_Estrutura_Terreno.ifc; ConstructionBasis: DESIGN_ASSUMPTION; Note: Concept gabion envelope; mesh gauge, foundation, filter and retaining capacity to design.
Pset_CasaBoundary - BaseSurveyLevel_m: 15.269; TopSurveyLevel_m: 16.0325; Status: CONCEPT_NOT_SIZED

# IfcWall: Acesso · gabião 1 24.0 · núcleo de pedra
In: Lares · Rua das Mercês · artigo 4771
PredefinedType: USERDEFINED; Material: Gabião · enchimento
Pset_CasaProvenance - DesignSource: Casa Sobreposta / configuration.json; ReferenceFile: 260617_CasaDFL_Estrutura_Terreno.ifc; ConstructionBasis: DESIGN_ASSUMPTION; Note: Concept gabion envelope; mesh gauge, foundation, filter and retaining capacity to design.
Pset_CasaBoundary - BaseSurveyLevel_m: 15.3909; TopSurveyLevel_m: 16.2135; Status: CONCEPT_NOT_SIZED

# IfcWall: Acesso · gabião 1 27.0 · núcleo de pedra
In: Lares · Rua das Mercês · artigo 4771
PredefinedType: USERDEFINED; Material: Gabião · enchimento
Pset_CasaProvenance - DesignSource: Casa Sobreposta / configuration.json; ReferenceFile: 260617_CasaDFL_Estrutura_Terreno.ifc; ConstructionBasis: DESIGN_ASSUMPTION; Note: Concept gabion envelope; mesh gauge, foundation, filter and retaining capacity to design.
Pset_CasaBoundary - BaseSurveyLevel_m: 15.5433; TopSurveyLevel_m: 16.3757; Status: CONCEPT_NOT_SIZED

# IfcWall: Acesso · gabião 1 30.0 · núcleo de pedra
In: Lares · Rua das Mercês · artigo 4771
PredefinedType: USERDEFINED; Material: Gabião · enchimento
Pset_CasaProvenance - DesignSource: Casa Sobreposta / configuration.json; ReferenceFile: 260617_CasaDFL_Estrutura_Terreno.ifc; ConstructionBasis: DESIGN_ASSUMPTION; Note: Concept gabion envelope; mesh gauge, foundation, filter and retaining capacity to design.
Pset_CasaBoundary - BaseSurveyLevel_m: 15.7042; TopSurveyLevel_m: 16.5071; Status: CONCEPT_NOT_SIZED

# IfcWall: Acesso · gabião 1 33.0 · núcleo de pedra
In: Lares · Rua das Mercês · artigo 4771
PredefinedType: USERDEFINED; Material: Gabião · enchimento
Pset_CasaProvenance - DesignSource: Casa Sobreposta / configuration.json; ReferenceFile: 260617_CasaDFL_Estrutura_Terreno.ifc; ConstructionBasis: DESIGN_ASSUMPTION; Note: Concept gabion envelope; mesh gauge, foundation, filter and retaining capacity to design.
Pset_CasaBoundary - BaseSurveyLevel_m: 15.8287; TopSurveyLevel_m: 16.6061; Status: CONCEPT_NOT_SIZED

# IfcWall: Acesso · gabião 1 9.0 · núcleo de pedra
In: Lares · Rua das Mercês · artigo 4771
PredefinedType: USERDEFINED; Material: Gabião · enchimento
Pset_CasaProvenance - DesignSource: Casa Sobreposta / configuration.json; ReferenceFile: 260617_CasaDFL_Estrutura_Terreno.ifc; ConstructionBasis: DESIGN_ASSUMPTION; Note: Concept gabion envelope; mesh gauge, foundation, filter and retaining capacity to design.
Pset_CasaBoundary - BaseSurveyLevel_m: 14.8084; TopSurveyLevel_m: 15.73; Status: CONCEPT_NOT_SIZED

# IfcWall: Cisterna · parede nascente
In: -01 · Cisterna sob o terraço
PredefinedType: USERDEFINED; Material: Betão armado / Stahlbeton
Pset_CasaProvenance - DesignSource: Casa Sobreposta / configuration.json; ReferenceFile: 260617_CasaDFL_Estrutura_Terreno.ifc; ConstructionBasis: DESIGN_ASSUMPTION; Note: 250 mm RC study wall, waterproofing and joints to detail; no retaining capacity asserted.

# IfcWall: Cisterna · parede norte
In: -01 · Cisterna sob o terraço
PredefinedType: USERDEFINED; Material: Betão armado / Stahlbeton
Pset_CasaProvenance - DesignSource: Casa Sobreposta / configuration.json; ReferenceFile: 260617_CasaDFL_Estrutura_Terreno.ifc; ConstructionBasis: DESIGN_ASSUMPTION; Note: 250 mm RC study wall, waterproofing and joints to detail; no retaining capacity asserted.

# IfcWall: Cisterna · parede poente
In: -01 · Cisterna sob o terraço
PredefinedType: USERDEFINED; Material: Betão armado / Stahlbeton
Pset_CasaProvenance - DesignSource: Casa Sobreposta / configuration.json; ReferenceFile: 260617_CasaDFL_Estrutura_Terreno.ifc; ConstructionBasis: DESIGN_ASSUMPTION; Note: 250 mm RC study wall, waterproofing and joints to detail; no retaining capacity asserted.

# IfcWall: Cisterna · parede sul
In: -01 · Cisterna sob o terraço
PredefinedType: USERDEFINED; Material: Betão armado / Stahlbeton
Pset_CasaProvenance - DesignSource: Casa Sobreposta / configuration.json; ReferenceFile: 260617_CasaDFL_Estrutura_Terreno.ifc; ConstructionBasis: DESIGN_ASSUMPTION; Note: 250 mm RC study wall, waterproofing and joints to detail; no retaining capacity asserted.

# IfcWall: Limite north · gabião 10 · núcleo de pedra
In: Lares · Rua das Mercês · artigo 4771
PredefinedType: USERDEFINED; Material: Gabião · enchimento
Pset_CasaProvenance - DesignSource: Casa Sobreposta / configuration.json; ReferenceFile: 260617_CasaDFL_Estrutura_Terreno.ifc; ConstructionBasis: DESIGN_ASSUMPTION; Note: Concept gabion envelope; mesh gauge, foundation, filter and retaining capacity to design.
Pset_CasaBoundary - BaseSurveyLevel_m: 14; TopSurveyLevel_m: 14.9; Status: CONCEPT_NOT_SIZED

# IfcWall: Limite north · gabião 11 · núcleo de pedra
In: Lares · Rua das Mercês · artigo 4771
PredefinedType: USERDEFINED; Material: Gabião · enchimento
Pset_CasaProvenance - DesignSource: Casa Sobreposta / configuration.json; ReferenceFile: 260617_CasaDFL_Estrutura_Terreno.ifc; ConstructionBasis: DESIGN_ASSUMPTION; Note: Concept gabion envelope; mesh gauge, foundation, filter and retaining capacity to design.
Pset_CasaBoundary - BaseSurveyLevel_m: 14.25; TopSurveyLevel_m: 15; Status: CONCEPT_NOT_SIZED

# IfcWall: Limite north · gabião 12 · núcleo de pedra
In: Lares · Rua das Mercês · artigo 4771
PredefinedType: USERDEFINED; Material: Gabião · enchimento
Pset_CasaProvenance - DesignSource: Casa Sobreposta / configuration.json; ReferenceFile: 260617_CasaDFL_Estrutura_Terreno.ifc; ConstructionBasis: DESIGN_ASSUMPTION; Note: Concept gabion envelope; mesh gauge, foundation, filter and retaining capacity to design.
Pset_CasaBoundary - BaseSurveyLevel_m: 14.25; TopSurveyLevel_m: 15.1; Status: CONCEPT_NOT_SIZED

# IfcWall: Limite north · gabião 13 · núcleo de pedra
In: Lares · Rua das Mercês · artigo 4771
PredefinedType: USERDEFINED; Material: Gabião · enchimento
Pset_CasaProvenance - DesignSource: Casa Sobreposta / configuration.json; ReferenceFile: 260617_CasaDFL_Estrutura_Terreno.ifc; ConstructionBasis: DESIGN_ASSUMPTION; Note: Concept gabion envelope; mesh gauge, foundation, filter and retaining capacity to design.
Pset_CasaBoundary - BaseSurveyLevel_m: 14.25; TopSurveyLevel_m: 15.2; Status: CONCEPT_NOT_SIZED

# IfcWall: Limite north · gabião 14 · núcleo de pedra
In: Lares · Rua das Mercês · artigo 4771
PredefinedType: USERDEFINED; Material: Gabião · enchimento
Pset_CasaProvenance - DesignSource: Casa Sobreposta / configuration.json; ReferenceFile: 260617_CasaDFL_Estrutura_Terreno.ifc; ConstructionBasis: DESIGN_ASSUMPTION; Note: Concept gabion envelope; mesh gauge, foundation, filter and retaining capacity to design.
Pset_CasaBoundary - BaseSurveyLevel_m: 14.5; TopSurveyLevel_m: 15.3; Status: CONCEPT_NOT_SIZED

# IfcWall: Limite north · gabião 15 · núcleo de pedra
In: Lares · Rua das Mercês · artigo 4771
PredefinedType: USERDEFINED; Material: Gabião · enchimento
Pset_CasaProvenance - DesignSource: Casa Sobreposta / configuration.json; ReferenceFile: 260617_CasaDFL_Estrutura_Terreno.ifc; ConstructionBasis: DESIGN_ASSUMPTION; Note: Concept gabion envelope; mesh gauge, foundation, filter and retaining capacity to design.
Pset_CasaBoundary - BaseSurveyLevel_m: 14.5; TopSurveyLevel_m: 15.5; Status: CONCEPT_NOT_SIZED

# IfcWall: Limite north · gabião 16 · núcleo de pedra
In: Lares · Rua das Mercês · artigo 4771
PredefinedType: USERDEFINED; Material: Gabião · enchimento
Pset_CasaProvenance - DesignSource: Casa Sobreposta / configuration.json; ReferenceFile: 260617_CasaDFL_Estrutura_Terreno.ifc; ConstructionBasis: DESIGN_ASSUMPTION; Note: Concept gabion envelope; mesh gauge, foundation, filter and retaining capacity to design.
Pset_CasaBoundary - BaseSurveyLevel_m: 14.75; TopSurveyLevel_m: 15.5; Status: CONCEPT_NOT_SIZED

# IfcWall: Limite north · gabião 17 · núcleo de pedra
In: Lares · Rua das Mercês · artigo 4771
PredefinedType: USERDEFINED; Material: Gabião · enchimento
Pset_CasaProvenance - DesignSource: Casa Sobreposta / configuration.json; ReferenceFile: 260617_CasaDFL_Estrutura_Terreno.ifc; ConstructionBasis: DESIGN_ASSUMPTION; Note: Concept gabion envelope; mesh gauge, foundation, filter and retaining capacity to design.
Pset_CasaBoundary - BaseSurveyLevel_m: 14.75; TopSurveyLevel_m: 15.6; Status: CONCEPT_NOT_SIZED

# IfcWall: Limite north · gabião 18 · núcleo de pedra
In: Lares · Rua das Mercês · artigo 4771
PredefinedType: USERDEFINED; Material: Gabião · enchimento
Pset_CasaProvenance - DesignSource: Casa Sobreposta / configuration.json; ReferenceFile: 260617_CasaDFL_Estrutura_Terreno.ifc; ConstructionBasis: DESIGN_ASSUMPTION; Note: Concept gabion envelope; mesh gauge, foundation, filter and retaining capacity to design.
Pset_CasaBoundary - BaseSurveyLevel_m: 14.75; TopSurveyLevel_m: 15.6; Status: CONCEPT_NOT_SIZED

# IfcWall: Limite north · gabião 19 · núcleo de pedra
In: Lares · Rua das Mercês · artigo 4771
PredefinedType: USERDEFINED; Material: Gabião · enchimento
Pset_CasaProvenance - DesignSource: Casa Sobreposta / configuration.json; ReferenceFile: 260617_CasaDFL_Estrutura_Terreno.ifc; ConstructionBasis: DESIGN_ASSUMPTION; Note: Concept gabion envelope; mesh gauge, foundation, filter and retaining capacity to design.
Pset_CasaBoundary - BaseSurveyLevel_m: 14.75; TopSurveyLevel_m: 15.7; Status: CONCEPT_NOT_SIZED

# IfcWall: Limite north · gabião 20 · núcleo de pedra
In: Lares · Rua das Mercês · artigo 4771
PredefinedType: USERDEFINED; Material: Gabião · enchimento
Pset_CasaProvenance - DesignSource: Casa Sobreposta / configuration.json; ReferenceFile: 260617_CasaDFL_Estrutura_Terreno.ifc; ConstructionBasis: DESIGN_ASSUMPTION; Note: Concept gabion envelope; mesh gauge, foundation, filter and retaining capacity to design.
Pset_CasaBoundary - BaseSurveyLevel_m: 15; TopSurveyLevel_m: 15.7; Status: CONCEPT_NOT_SIZED

# IfcWall: Limite north · gabião 21 · núcleo de pedra
In: Lares · Rua das Mercês · artigo 4771
PredefinedType: USERDEFINED; Material: Gabião · enchimento
Pset_CasaProvenance - DesignSource: Casa Sobreposta / configuration.json; ReferenceFile: 260617_CasaDFL_Estrutura_Terreno.ifc; ConstructionBasis: DESIGN_ASSUMPTION; Note: Concept gabion envelope; mesh gauge, foundation, filter and retaining capacity to design.
Pset_CasaBoundary - BaseSurveyLevel_m: 15; TopSurveyLevel_m: 15.9; Status: CONCEPT_NOT_SIZED

# IfcWall: Limite north · gabião 22 · núcleo de pedra
In: Lares · Rua das Mercês · artigo 4771
PredefinedType: USERDEFINED; Material: Gabião · enchimento
Pset_CasaProvenance - DesignSource: Casa Sobreposta / configuration.json; ReferenceFile: 260617_CasaDFL_Estrutura_Terreno.ifc; ConstructionBasis: DESIGN_ASSUMPTION; Note: Concept gabion envelope; mesh gauge, foundation, filter and retaining capacity to design.
Pset_CasaBoundary - BaseSurveyLevel_m: 15.25; TopSurveyLevel_m: 16.1; Status: CONCEPT_NOT_SIZED

# IfcWall: Limite north · gabião 23 · núcleo de pedra
In: Lares · Rua das Mercês · artigo 4771
PredefinedType: USERDEFINED; Material: Gabião · enchimento
Pset_CasaProvenance - DesignSource: Casa Sobreposta / configuration.json; ReferenceFile: 260617_CasaDFL_Estrutura_Terreno.ifc; ConstructionBasis: DESIGN_ASSUMPTION; Note: Concept gabion envelope; mesh gauge, foundation, filter and retaining capacity to design.
Pset_CasaBoundary - BaseSurveyLevel_m: 15.25; TopSurveyLevel_m: 16.3; Status: CONCEPT_NOT_SIZED

# IfcWall: Limite north · gabião 24 · núcleo de pedra
In: Lares · Rua das Mercês · artigo 4771
PredefinedType: USERDEFINED; Material: Gabião · enchimento
Pset_CasaProvenance - DesignSource: Casa Sobreposta / configuration.json; ReferenceFile: 260617_CasaDFL_Estrutura_Terreno.ifc; ConstructionBasis: DESIGN_ASSUMPTION; Note: Concept gabion envelope; mesh gauge, foundation, filter and retaining capacity to design.
Pset_CasaBoundary - BaseSurveyLevel_m: 15.5; TopSurveyLevel_m: 16.5; Status: CONCEPT_NOT_SIZED

# IfcWall: Limite north · gabião 25 · núcleo de pedra
In: Lares · Rua das Mercês · artigo 4771
PredefinedType: USERDEFINED; Material: Gabião · enchimento
Pset_CasaProvenance - DesignSource: Casa Sobreposta / configuration.json; ReferenceFile: 260617_CasaDFL_Estrutura_Terreno.ifc; ConstructionBasis: DESIGN_ASSUMPTION; Note: Concept gabion envelope; mesh gauge, foundation, filter and retaining capacity to design.
Pset_CasaBoundary - BaseSurveyLevel_m: 15.75; TopSurveyLevel_m: 16.6; Status: CONCEPT_NOT_SIZED

# IfcWall: Limite north · gabião 26 · núcleo de pedra
In: Lares · Rua das Mercês · artigo 4771
PredefinedType: USERDEFINED; Material: Gabião · enchimento
Pset_CasaProvenance - DesignSource: Casa Sobreposta / configuration.json; ReferenceFile: 260617_CasaDFL_Estrutura_Terreno.ifc; ConstructionBasis: DESIGN_ASSUMPTION; Note: Concept gabion envelope; mesh gauge, foundation, filter and retaining capacity to design.
Pset_CasaBoundary - BaseSurveyLevel_m: 15.75; TopSurveyLevel_m: 16.8; Status: CONCEPT_NOT_SIZED

# IfcWall: Limite north · gabião 27 · núcleo de pedra
In: Lares · Rua das Mercês · artigo 4771
PredefinedType: USERDEFINED; Material: Gabião · enchimento
Pset_CasaProvenance - DesignSource: Casa Sobreposta / configuration.json; ReferenceFile: 260617_CasaDFL_Estrutura_Terreno.ifc; ConstructionBasis: DESIGN_ASSUMPTION; Note: Concept gabion envelope; mesh gauge, foundation, filter and retaining capacity to design.
Pset_CasaBoundary - BaseSurveyLevel_m: 16; TopSurveyLevel_m: 16.9; Status: CONCEPT_NOT_SIZED

# IfcWall: Limite north · gabião 4 · núcleo de pedra
In: Lares · Rua das Mercês · artigo 4771
PredefinedType: USERDEFINED; Material: Gabião · enchimento
Pset_CasaProvenance - DesignSource: Casa Sobreposta / configuration.json; ReferenceFile: 260617_CasaDFL_Estrutura_Terreno.ifc; ConstructionBasis: DESIGN_ASSUMPTION; Note: Concept gabion envelope; mesh gauge, foundation, filter and retaining capacity to design.
Pset_CasaBoundary - BaseSurveyLevel_m: 13.25; TopSurveyLevel_m: 14.3; Status: CONCEPT_NOT_SIZED

# IfcWall: Limite north · gabião 5 · núcleo de pedra
In: Lares · Rua das Mercês · artigo 4771
PredefinedType: USERDEFINED; Material: Gabião · enchimento
Pset_CasaProvenance - DesignSource: Casa Sobreposta / configuration.json; ReferenceFile: 260617_CasaDFL_Estrutura_Terreno.ifc; ConstructionBasis: DESIGN_ASSUMPTION; Note: Concept gabion envelope; mesh gauge, foundation, filter and retaining capacity to design.
Pset_CasaBoundary - BaseSurveyLevel_m: 13.5; TopSurveyLevel_m: 14.3; Status: CONCEPT_NOT_SIZED

# IfcWall: Limite north · gabião 6 · núcleo de pedra
In: Lares · Rua das Mercês · artigo 4771
PredefinedType: USERDEFINED; Material: Gabião · enchimento
Pset_CasaProvenance - DesignSource: Casa Sobreposta / configuration.json; ReferenceFile: 260617_CasaDFL_Estrutura_Terreno.ifc; ConstructionBasis: DESIGN_ASSUMPTION; Note: Concept gabion envelope; mesh gauge, foundation, filter and retaining capacity to design.
Pset_CasaBoundary - BaseSurveyLevel_m: 13.5; TopSurveyLevel_m: 14.5; Status: CONCEPT_NOT_SIZED

# IfcWall: Limite north · gabião 7 · núcleo de pedra
In: Lares · Rua das Mercês · artigo 4771
PredefinedType: USERDEFINED; Material: Gabião · enchimento
Pset_CasaProvenance - DesignSource: Casa Sobreposta / configuration.json; ReferenceFile: 260617_CasaDFL_Estrutura_Terreno.ifc; ConstructionBasis: DESIGN_ASSUMPTION; Note: Concept gabion envelope; mesh gauge, foundation, filter and retaining capacity to design.
Pset_CasaBoundary - BaseSurveyLevel_m: 13.75; TopSurveyLevel_m: 14.7; Status: CONCEPT_NOT_SIZED

# IfcWall: Limite north · gabião 8 · núcleo de pedra
In: Lares · Rua das Mercês · artigo 4771
PredefinedType: USERDEFINED; Material: Gabião · enchimento
Pset_CasaProvenance - DesignSource: Casa Sobreposta / configuration.json; ReferenceFile: 260617_CasaDFL_Estrutura_Terreno.ifc; ConstructionBasis: DESIGN_ASSUMPTION; Note: Concept gabion envelope; mesh gauge, foundation, filter and retaining capacity to design.
Pset_CasaBoundary - BaseSurveyLevel_m: 14; TopSurveyLevel_m: 14.7; Status: CONCEPT_NOT_SIZED

# IfcWall: Limite north · gabião 9 · núcleo de pedra
In: Lares · Rua das Mercês · artigo 4771
PredefinedType: USERDEFINED; Material: Gabião · enchimento
Pset_CasaProvenance - DesignSource: Casa Sobreposta / configuration.json; ReferenceFile: 260617_CasaDFL_Estrutura_Terreno.ifc; ConstructionBasis: DESIGN_ASSUMPTION; Note: Concept gabion envelope; mesh gauge, foundation, filter and retaining capacity to design.
Pset_CasaBoundary - BaseSurveyLevel_m: 14; TopSurveyLevel_m: 14.8; Status: CONCEPT_NOT_SIZED

# IfcWall: Limite south · gabião 1 · núcleo de pedra
In: Lares · Rua das Mercês · artigo 4771
PredefinedType: USERDEFINED; Material: Gabião · enchimento
Pset_CasaProvenance - DesignSource: Casa Sobreposta / configuration.json; ReferenceFile: 260617_CasaDFL_Estrutura_Terreno.ifc; ConstructionBasis: DESIGN_ASSUMPTION; Note: Concept gabion envelope; mesh gauge, foundation, filter and retaining capacity to design.
Pset_CasaBoundary - BaseSurveyLevel_m: 10.25; TopSurveyLevel_m: 11.2; Status: CONCEPT_NOT_SIZED

# IfcWall: Limite south · gabião 10 · núcleo de pedra
In: Lares · Rua das Mercês · artigo 4771
PredefinedType: USERDEFINED; Material: Gabião · enchimento
Pset_CasaProvenance - DesignSource: Casa Sobreposta / configuration.json; ReferenceFile: 260617_CasaDFL_Estrutura_Terreno.ifc; ConstructionBasis: DESIGN_ASSUMPTION; Note: Concept gabion envelope; mesh gauge, foundation, filter and retaining capacity to design.
Pset_CasaBoundary - BaseSurveyLevel_m: 11.5; TopSurveyLevel_m: 12.6; Status: CONCEPT_NOT_SIZED

# IfcWall: Limite south · gabião 11 · núcleo de pedra
In: Lares · Rua das Mercês · artigo 4771
PredefinedType: USERDEFINED; Material: Gabião · enchimento
Pset_CasaProvenance - DesignSource: Casa Sobreposta / configuration.json; ReferenceFile: 260617_CasaDFL_Estrutura_Terreno.ifc; ConstructionBasis: DESIGN_ASSUMPTION; Note: Concept gabion envelope; mesh gauge, foundation, filter and retaining capacity to design.
Pset_CasaBoundary - BaseSurveyLevel_m: 11.75; TopSurveyLevel_m: 12.8; Status: CONCEPT_NOT_SIZED

# IfcWall: Limite south · gabião 12 · núcleo de pedra
In: Lares · Rua das Mercês · artigo 4771
PredefinedType: USERDEFINED; Material: Gabião · enchimento
Pset_CasaProvenance - DesignSource: Casa Sobreposta / configuration.json; ReferenceFile: 260617_CasaDFL_Estrutura_Terreno.ifc; ConstructionBasis: DESIGN_ASSUMPTION; Note: Concept gabion envelope; mesh gauge, foundation, filter and retaining capacity to design.
Pset_CasaBoundary - BaseSurveyLevel_m: 11.75; TopSurveyLevel_m: 12.8; Status: CONCEPT_NOT_SIZED

# IfcWall: Limite south · gabião 13 · núcleo de pedra
In: Lares · Rua das Mercês · artigo 4771
PredefinedType: USERDEFINED; Material: Gabião · enchimento
Pset_CasaProvenance - DesignSource: Casa Sobreposta / configuration.json; ReferenceFile: 260617_CasaDFL_Estrutura_Terreno.ifc; ConstructionBasis: DESIGN_ASSUMPTION; Note: Concept gabion envelope; mesh gauge, foundation, filter and retaining capacity to design.
Pset_CasaBoundary - BaseSurveyLevel_m: 12; TopSurveyLevel_m: 13; Status: CONCEPT_NOT_SIZED

# IfcWall: Limite south · gabião 14 · núcleo de pedra
In: Lares · Rua das Mercês · artigo 4771
PredefinedType: USERDEFINED; Material: Gabião · enchimento
Pset_CasaProvenance - DesignSource: Casa Sobreposta / configuration.json; ReferenceFile: 260617_CasaDFL_Estrutura_Terreno.ifc; ConstructionBasis: DESIGN_ASSUMPTION; Note: Concept gabion envelope; mesh gauge, foundation, filter and retaining capacity to design.
Pset_CasaBoundary - BaseSurveyLevel_m: 12; TopSurveyLevel_m: 13.1; Status: CONCEPT_NOT_SIZED

# IfcWall: Limite south · gabião 15 · núcleo de pedra
In: Lares · Rua das Mercês · artigo 4771
PredefinedType: USERDEFINED; Material: Gabião · enchimento
Pset_CasaProvenance - DesignSource: Casa Sobreposta / configuration.json; ReferenceFile: 260617_CasaDFL_Estrutura_Terreno.ifc; ConstructionBasis: DESIGN_ASSUMPTION; Note: Concept gabion envelope; mesh gauge, foundation, filter and retaining capacity to design.
Pset_CasaBoundary - BaseSurveyLevel_m: 12.25; TopSurveyLevel_m: 13.3; Status: CONCEPT_NOT_SIZED

# IfcWall: Limite south · gabião 16 · núcleo de pedra
In: Lares · Rua das Mercês · artigo 4771
PredefinedType: USERDEFINED; Material: Gabião · enchimento
Pset_CasaProvenance - DesignSource: Casa Sobreposta / configuration.json; ReferenceFile: 260617_CasaDFL_Estrutura_Terreno.ifc; ConstructionBasis: DESIGN_ASSUMPTION; Note: Concept gabion envelope; mesh gauge, foundation, filter and retaining capacity to design.
Pset_CasaBoundary - BaseSurveyLevel_m: 12.25; TopSurveyLevel_m: 13.3; Status: CONCEPT_NOT_SIZED

# IfcWall: Limite south · gabião 17 · núcleo de pedra
In: Lares · Rua das Mercês · artigo 4771
PredefinedType: USERDEFINED; Material: Gabião · enchimento
Pset_CasaProvenance - DesignSource: Casa Sobreposta / configuration.json; ReferenceFile: 260617_CasaDFL_Estrutura_Terreno.ifc; ConstructionBasis: DESIGN_ASSUMPTION; Note: Concept gabion envelope; mesh gauge, foundation, filter and retaining capacity to design.
Pset_CasaBoundary - BaseSurveyLevel_m: 12.5; TopSurveyLevel_m: 13.4; Status: CONCEPT_NOT_SIZED

# IfcWall: Limite south · gabião 18 · núcleo de pedra
In: Lares · Rua das Mercês · artigo 4771
PredefinedType: USERDEFINED; Material: Gabião · enchimento
Pset_CasaProvenance - DesignSource: Casa Sobreposta / configuration.json; ReferenceFile: 260617_CasaDFL_Estrutura_Terreno.ifc; ConstructionBasis: DESIGN_ASSUMPTION; Note: Concept gabion envelope; mesh gauge, foundation, filter and retaining capacity to design.
Pset_CasaBoundary - BaseSurveyLevel_m: 12.5; TopSurveyLevel_m: 13.6; Status: CONCEPT_NOT_SIZED

# IfcWall: Limite south · gabião 19 · núcleo de pedra
In: Lares · Rua das Mercês · artigo 4771
PredefinedType: USERDEFINED; Material: Gabião · enchimento
Pset_CasaProvenance - DesignSource: Casa Sobreposta / configuration.json; ReferenceFile: 260617_CasaDFL_Estrutura_Terreno.ifc; ConstructionBasis: DESIGN_ASSUMPTION; Note: Concept gabion envelope; mesh gauge, foundation, filter and retaining capacity to design.
Pset_CasaBoundary - BaseSurveyLevel_m: 12.75; TopSurveyLevel_m: 13.7; Status: CONCEPT_NOT_SIZED

# IfcWall: Limite south · gabião 2 · núcleo de pedra
In: Lares · Rua das Mercês · artigo 4771
PredefinedType: USERDEFINED; Material: Gabião · enchimento
Pset_CasaProvenance - DesignSource: Casa Sobreposta / configuration.json; ReferenceFile: 260617_CasaDFL_Estrutura_Terreno.ifc; ConstructionBasis: DESIGN_ASSUMPTION; Note: Concept gabion envelope; mesh gauge, foundation, filter and retaining capacity to design.
Pset_CasaBoundary - BaseSurveyLevel_m: 10.25; TopSurveyLevel_m: 11.3; Status: CONCEPT_NOT_SIZED

# IfcWall: Limite south · gabião 20 · núcleo de pedra
In: Lares · Rua das Mercês · artigo 4771
PredefinedType: USERDEFINED; Material: Gabião · enchimento
Pset_CasaProvenance - DesignSource: Casa Sobreposta / configuration.json; ReferenceFile: 260617_CasaDFL_Estrutura_Terreno.ifc; ConstructionBasis: DESIGN_ASSUMPTION; Note: Concept gabion envelope; mesh gauge, foundation, filter and retaining capacity to design.
Pset_CasaBoundary - BaseSurveyLevel_m: 12.75; TopSurveyLevel_m: 13.8; Status: CONCEPT_NOT_SIZED

# IfcWall: Limite south · gabião 21 · núcleo de pedra
In: Lares · Rua das Mercês · artigo 4771
PredefinedType: USERDEFINED; Material: Gabião · enchimento
Pset_CasaProvenance - DesignSource: Casa Sobreposta / configuration.json; ReferenceFile: 260617_CasaDFL_Estrutura_Terreno.ifc; ConstructionBasis: DESIGN_ASSUMPTION; Note: Concept gabion envelope; mesh gauge, foundation, filter and retaining capacity to design.
Pset_CasaBoundary - BaseSurveyLevel_m: 12.75; TopSurveyLevel_m: 13.9; Status: CONCEPT_NOT_SIZED

# IfcWall: Limite south · gabião 22 · núcleo de pedra
In: Lares · Rua das Mercês · artigo 4771
PredefinedType: USERDEFINED; Material: Gabião · enchimento
Pset_CasaProvenance - DesignSource: Casa Sobreposta / configuration.json; ReferenceFile: 260617_CasaDFL_Estrutura_Terreno.ifc; ConstructionBasis: DESIGN_ASSUMPTION; Note: Concept gabion envelope; mesh gauge, foundation, filter and retaining capacity to design.
Pset_CasaBoundary - BaseSurveyLevel_m: 13; TopSurveyLevel_m: 14.1; Status: CONCEPT_NOT_SIZED

# IfcWall: Limite south · gabião 23 · núcleo de pedra
In: Lares · Rua das Mercês · artigo 4771
PredefinedType: USERDEFINED; Material: Gabião · enchimento
Pset_CasaProvenance - DesignSource: Casa Sobreposta / configuration.json; ReferenceFile: 260617_CasaDFL_Estrutura_Terreno.ifc; ConstructionBasis: DESIGN_ASSUMPTION; Note: Concept gabion envelope; mesh gauge, foundation, filter and retaining capacity to design.
Pset_CasaBoundary - BaseSurveyLevel_m: 13.25; TopSurveyLevel_m: 14.3; Status: CONCEPT_NOT_SIZED

# IfcWall: Limite south · gabião 24 · núcleo de pedra
In: Lares · Rua das Mercês · artigo 4771
PredefinedType: USERDEFINED; Material: Gabião · enchimento
Pset_CasaProvenance - DesignSource: Casa Sobreposta / configuration.json; ReferenceFile: 260617_CasaDFL_Estrutura_Terreno.ifc; ConstructionBasis: DESIGN_ASSUMPTION; Note: Concept gabion envelope; mesh gauge, foundation, filter and retaining capacity to design.
Pset_CasaBoundary - BaseSurveyLevel_m: 13.25; TopSurveyLevel_m: 14.4; Status: CONCEPT_NOT_SIZED

# IfcWall: Limite south · gabião 25 · núcleo de pedra
In: Lares · Rua das Mercês · artigo 4771
PredefinedType: USERDEFINED; Material: Gabião · enchimento
Pset_CasaProvenance - DesignSource: Casa Sobreposta / configuration.json; ReferenceFile: 260617_CasaDFL_Estrutura_Terreno.ifc; ConstructionBasis: DESIGN_ASSUMPTION; Note: Concept gabion envelope; mesh gauge, foundation, filter and retaining capacity to design.
Pset_CasaBoundary - BaseSurveyLevel_m: 13.5; TopSurveyLevel_m: 14.6; Status: CONCEPT_NOT_SIZED

# IfcWall: Limite south · gabião 26 · núcleo de pedra
In: Lares · Rua das Mercês · artigo 4771
PredefinedType: USERDEFINED; Material: Gabião · enchimento
Pset_CasaProvenance - DesignSource: Casa Sobreposta / configuration.json; ReferenceFile: 260617_CasaDFL_Estrutura_Terreno.ifc; ConstructionBasis: DESIGN_ASSUMPTION; Note: Concept gabion envelope; mesh gauge, foundation, filter and retaining capacity to design.
Pset_CasaBoundary - BaseSurveyLevel_m: 13.75; TopSurveyLevel_m: 14.8; Status: CONCEPT_NOT_SIZED

# IfcWall: Limite south · gabião 27 · núcleo de pedra
In: Lares · Rua das Mercês · artigo 4771
PredefinedType: USERDEFINED; Material: Gabião · enchimento
Pset_CasaProvenance - DesignSource: Casa Sobreposta / configuration.json; ReferenceFile: 260617_CasaDFL_Estrutura_Terreno.ifc; ConstructionBasis: DESIGN_ASSUMPTION; Note: Concept gabion envelope; mesh gauge, foundation, filter and retaining capacity to design.
Pset_CasaBoundary - BaseSurveyLevel_m: 14; TopSurveyLevel_m: 15; Status: CONCEPT_NOT_SIZED

# IfcWall: Limite south · gabião 28 · núcleo de pedra
In: Lares · Rua das Mercês · artigo 4771
PredefinedType: USERDEFINED; Material: Gabião · enchimento
Pset_CasaProvenance - DesignSource: Casa Sobreposta / configuration.json; ReferenceFile: 260617_CasaDFL_Estrutura_Terreno.ifc; ConstructionBasis: DESIGN_ASSUMPTION; Note: Concept gabion envelope; mesh gauge, foundation, filter and retaining capacity to design.
Pset_CasaBoundary - BaseSurveyLevel_m: 14; TopSurveyLevel_m: 15.2; Status: CONCEPT_NOT_SIZED

# IfcWall: Limite south · gabião 29 · núcleo de pedra
In: Lares · Rua das Mercês · artigo 4771
PredefinedType: USERDEFINED; Material: Gabião · enchimento
Pset_CasaProvenance - DesignSource: Casa Sobreposta / configuration.json; ReferenceFile: 260617_CasaDFL_Estrutura_Terreno.ifc; ConstructionBasis: DESIGN_ASSUMPTION; Note: Concept gabion envelope; mesh gauge, foundation, filter and retaining capacity to design.
Pset_CasaBoundary - BaseSurveyLevel_m: 14.25; TopSurveyLevel_m: 15.4; Status: CONCEPT_NOT_SIZED

# IfcWall: Limite south · gabião 3 · núcleo de pedra
In: Lares · Rua das Mercês · artigo 4771
PredefinedType: USERDEFINED; Material: Gabião · enchimento
Pset_CasaProvenance - DesignSource: Casa Sobreposta / configuration.json; ReferenceFile: 260617_CasaDFL_Estrutura_Terreno.ifc; ConstructionBasis: DESIGN_ASSUMPTION; Note: Concept gabion envelope; mesh gauge, foundation, filter and retaining capacity to design.
Pset_CasaBoundary - BaseSurveyLevel_m: 10.25; TopSurveyLevel_m: 11.6; Status: CONCEPT_NOT_SIZED

# IfcWall: Limite south · gabião 30 · núcleo de pedra
In: Lares · Rua das Mercês · artigo 4771
PredefinedType: USERDEFINED; Material: Gabião · enchimento
Pset_CasaProvenance - DesignSource: Casa Sobreposta / configuration.json; ReferenceFile: 260617_CasaDFL_Estrutura_Terreno.ifc; ConstructionBasis: DESIGN_ASSUMPTION; Note: Concept gabion envelope; mesh gauge, foundation, filter and retaining capacity to design.
Pset_CasaBoundary - BaseSurveyLevel_m: 14.5; TopSurveyLevel_m: 15.6; Status: CONCEPT_NOT_SIZED

# IfcWall: Limite south · gabião 31 · núcleo de pedra
In: Lares · Rua das Mercês · artigo 4771
PredefinedType: USERDEFINED; Material: Gabião · enchimento
Pset_CasaProvenance - DesignSource: Casa Sobreposta / configuration.json; ReferenceFile: 260617_CasaDFL_Estrutura_Terreno.ifc; ConstructionBasis: DESIGN_ASSUMPTION; Note: Concept gabion envelope; mesh gauge, foundation, filter and retaining capacity to design.
Pset_CasaBoundary - BaseSurveyLevel_m: 14.75; TopSurveyLevel_m: 15.8; Status: CONCEPT_NOT_SIZED

# IfcWall: Limite south · gabião 4 · núcleo de pedra
In: Lares · Rua das Mercês · artigo 4771
PredefinedType: USERDEFINED; Material: Gabião · enchimento
Pset_CasaProvenance - DesignSource: Casa Sobreposta / configuration.json; ReferenceFile: 260617_CasaDFL_Estrutura_Terreno.ifc; ConstructionBasis: DESIGN_ASSUMPTION; Note: Concept gabion envelope; mesh gauge, foundation, filter and retaining capacity to design.
Pset_CasaBoundary - BaseSurveyLevel_m: 10.75; TopSurveyLevel_m: 11.9; Status: CONCEPT_NOT_SIZED

# IfcWall: Limite south · gabião 5 · núcleo de pedra
In: Lares · Rua das Mercês · artigo 4771
PredefinedType: USERDEFINED; Material: Gabião · enchimento
Pset_CasaProvenance - DesignSource: Casa Sobreposta / configuration.json; ReferenceFile: 260617_CasaDFL_Estrutura_Terreno.ifc; ConstructionBasis: DESIGN_ASSUMPTION; Note: Concept gabion envelope; mesh gauge, foundation, filter and retaining capacity to design.
Pset_CasaBoundary - BaseSurveyLevel_m: 11; TopSurveyLevel_m: 12; Status: CONCEPT_NOT_SIZED

# IfcWall: Limite south · gabião 6 · núcleo de pedra
In: Lares · Rua das Mercês · artigo 4771
PredefinedType: USERDEFINED; Material: Gabião · enchimento
Pset_CasaProvenance - DesignSource: Casa Sobreposta / configuration.json; ReferenceFile: 260617_CasaDFL_Estrutura_Terreno.ifc; ConstructionBasis: DESIGN_ASSUMPTION; Note: Concept gabion envelope; mesh gauge, foundation, filter and retaining capacity to design.
Pset_CasaBoundary - BaseSurveyLevel_m: 11; TopSurveyLevel_m: 12.1; Status: CONCEPT_NOT_SIZED

# IfcWall: Limite south · gabião 7 · núcleo de pedra
In: Lares · Rua das Mercês · artigo 4771
PredefinedType: USERDEFINED; Material: Gabião · enchimento
Pset_CasaProvenance - DesignSource: Casa Sobreposta / configuration.json; ReferenceFile: 260617_CasaDFL_Estrutura_Terreno.ifc; ConstructionBasis: DESIGN_ASSUMPTION; Note: Concept gabion envelope; mesh gauge, foundation, filter and retaining capacity to design.
Pset_CasaBoundary - BaseSurveyLevel_m: 11.25; TopSurveyLevel_m: 12.2; Status: CONCEPT_NOT_SIZED

# IfcWall: Limite south · gabião 8 · núcleo de pedra
In: Lares · Rua das Mercês · artigo 4771
PredefinedType: USERDEFINED; Material: Gabião · enchimento
Pset_CasaProvenance - DesignSource: Casa Sobreposta / configuration.json; ReferenceFile: 260617_CasaDFL_Estrutura_Terreno.ifc; ConstructionBasis: DESIGN_ASSUMPTION; Note: Concept gabion envelope; mesh gauge, foundation, filter and retaining capacity to design.
Pset_CasaBoundary - BaseSurveyLevel_m: 11.25; TopSurveyLevel_m: 12.4; Status: CONCEPT_NOT_SIZED

# IfcWall: Limite south · gabião 9 · núcleo de pedra
In: Lares · Rua das Mercês · artigo 4771
PredefinedType: USERDEFINED; Material: Gabião · enchimento
Pset_CasaProvenance - DesignSource: Casa Sobreposta / configuration.json; ReferenceFile: 260617_CasaDFL_Estrutura_Terreno.ifc; ConstructionBasis: DESIGN_ASSUMPTION; Note: Concept gabion envelope; mesh gauge, foundation, filter and retaining capacity to design.
Pset_CasaBoundary - BaseSurveyLevel_m: 11.5; TopSurveyLevel_m: 12.5; Status: CONCEPT_NOT_SIZED

# IfcWindow (58)
PredefinedType: WINDOW; PartitioningType: SINGLE_PANEL; Material: Vidro / Normalglas
Pset_CasaProvenance - DesignSource: Casa Sobreposta / configuration.json; ReferenceFile: 260617_CasaDFL_Estrutura_Terreno.ifc; ConstructionBasis: DESIGN_ASSUMPTION
Name | In | OverallHeight (m) | OverallWidth (m)
Rasgo norte 1 | 00 · Habitação e estacionamento | 0.3 | 3.79
Rasgo norte 2 | 00 · Habitação e estacionamento | 0.3 | 3.79
Rasgo norte 3 | 00 · Habitação e estacionamento | 0.3 | 3.79
Rasgo norte 4 | 00 · Habitação e estacionamento | 0.3 | 3.79
Rasgo norte 5 | 00 · Habitação e estacionamento | 0.3 | 3.79
Rasgo norte 6 | 00 · Habitação e estacionamento | 0.3 | 3.79
Rasgo norte 7 | 00 · Habitação e estacionamento | 0.3 | 0.71
Fachada poente integralmente envidraçada · módulo 1 | 00 · Habitação e estacionamento | 2.918 | 1.55 | Pset_CasaGlazedFacade - Revision: R02 · kiwi pergola; Facade: WEST / highlighted end in user sketch; Infill: Full-height glazing; no opaque infill; GlazingSpecification: 8 mm nominal representation only; insulated safety glazing assembly to specify
Fachada poente integralmente envidraçada · módulo 2 | 00 · Habitação e estacionamento | 2.918 | 1.55 | Pset_CasaGlazedFacade - Revision: R02 · kiwi pergola; Facade: WEST / highlighted end in user sketch; Infill: Full-height glazing; no opaque infill; GlazingSpecification: 8 mm nominal representation only; insulated safety glazing assembly to specify
Fachada poente integralmente envidraçada · módulo 3 | 00 · Habitação e estacionamento | 2.918 | 1.55 | Pset_CasaGlazedFacade - Revision: R02 · kiwi pergola; Facade: WEST / highlighted end in user sketch; Infill: Full-height glazing; no opaque infill; GlazingSpecification: 8 mm nominal representation only; insulated safety glazing assembly to specify
Estufa sul 1 | 01 · Jardim de inverno | 2.43 | 1.95
Estufa sul 2 | 01 · Jardim de inverno | 2.43 | 1.95
Estufa sul 3 | 01 · Jardim de inverno | 2.43 | 1.95
Estufa sul 4 | 01 · Jardim de inverno | 2.43 | 1.95
Estufa sul 5 | 01 · Jardim de inverno | 2.43 | 1.95
Estufa sul 6 | 01 · Jardim de inverno | 2.43 | 1.95
Estufa sul 7 | 01 · Jardim de inverno | 2.43 | 1.95
Estufa sul 8 | 01 · Jardim de inverno | 2.43 | 1.95
Estufa sul 9 | 01 · Jardim de inverno | 2.43 | 1.95
Estufa sul 10 | 01 · Jardim de inverno | 2.43 | 1.95
Estufa sul 11 | 01 · Jardim de inverno | 2.43 | 1.95
Estufa sul 12 | 01 · Jardim de inverno | 2.43 | 1.95
Estufa sul 13 | 01 · Jardim de inverno | 2.43 | 1.95
Estufa sul 14 | 01 · Jardim de inverno | 2.43 | 1.95
Estufa sul 15 | 01 · Jardim de inverno | 2.43 | 1.95
Estufa sul 16 | 01 · Jardim de inverno | 2.43 | 1.95
Estufa norte 1 | 01 · Jardim de inverno | 2.43 | 1.95
Estufa norte 2 | 01 · Jardim de inverno | 2.43 | 1.95
Estufa norte 3 | 01 · Jardim de inverno | 2.43 | 1.95
Estufa norte 4 | 01 · Jardim de inverno | 2.43 | 1.95
Estufa norte 5 | 01 · Jardim de inverno | 2.43 | 1.95
Estufa norte 6 | 01 · Jardim de inverno | 2.43 | 1.95
Estufa norte 7 | 01 · Jardim de inverno | 2.43 | 1.95
Estufa norte 8 | 01 · Jardim de inverno | 2.43 | 1.95
Estufa norte 9 | 01 · Jardim de inverno | 2.43 | 1.95
Estufa norte 10 | 01 · Jardim de inverno | 2.43 | 1.95
Estufa norte 11 | 01 · Jardim de inverno | 2.43 | 1.95
Estufa norte 12 | 01 · Jardim de inverno | 2.43 | 1.95
Estufa norte 13 | 01 · Jardim de inverno | 2.43 | 1.95
Estufa norte 14 | 01 · Jardim de inverno | 2.43 | 1.95
Estufa norte 15 | 01 · Jardim de inverno | 2.43 | 1.95
Estufa norte 16 | 01 · Jardim de inverno | 2.43 | 1.95
Varanda · bandeira da porta | 01 · Jardim de inverno | 0.73 | 1.05
Varanda · vidro lateral | 01 · Jardim de inverno | 2.93 | 0.1
Varanda · vidro lateral | 01 · Jardim de inverno | 2.93 | 0.675
Estufa poente 2 | 01 · Jardim de inverno | 2.93 | 1.925
Estufa poente 3 | 01 · Jardim de inverno | 2.93 | 1.925
Estufa poente 4 | 01 · Jardim de inverno | 2.93 | 1.925
Estufa nascente 1 | 01 · Jardim de inverno | 2.93 | 1.925
Estufa nascente 2 | 01 · Jardim de inverno | 2.93 | 1.925
Estufa nascente 3 | 01 · Jardim de inverno | 2.93 | 1.925
Estufa nascente 4 | 01 · Jardim de inverno | 2.93 | 1.925
Caixa térmica 1 · west | 01 · Jardim de inverno | 2.15 | 4.7
Caixa térmica 1 · east | 01 · Jardim de inverno | 2.15 | 4.7
Caixa térmica 1 · south | 01 · Jardim de inverno | 2.15 | 0.9
Caixa térmica 2 · west | 01 · Jardim de inverno | 2.15 | 4.7
Caixa térmica 2 · east | 01 · Jardim de inverno | 2.15 | 4.7
Caixa térmica 2 · north | 01 · Jardim de inverno | 2.15 | 0.91
